VERSION 5.7 ;
  NOWIREEXTENSIONATPIN ON ;
  DIVIDERCHAR "/" ;
  BUSBITCHARS "[]" ;
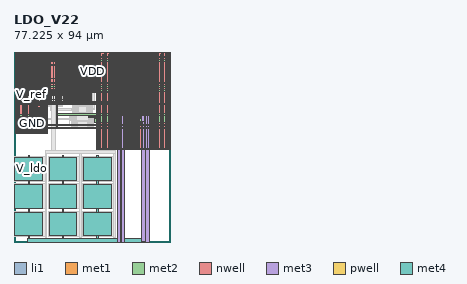
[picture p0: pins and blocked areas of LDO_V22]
MACRO LDO_V22
  CLASS BLOCK ;
  FOREIGN LDO_V22 ;
  ORIGIN -121.455 234.070 ;
  SIZE 77.225 BY 94.000 ;
  PIN V_ref
    ANTENNAGATEAREA 1.000000 ;
    PORT
      LAYER li1 ;
        RECT 125.885 -162.020 126.675 -161.850 ;
        RECT 127.175 -162.020 127.965 -161.850 ;
        RECT 125.885 -163.070 126.675 -162.900 ;
        RECT 127.175 -163.070 127.965 -162.900 ;
      LAYER met1 ;
        RECT 125.960 -161.820 126.600 -161.730 ;
        RECT 127.250 -161.820 127.890 -161.730 ;
        RECT 125.905 -162.050 126.655 -161.820 ;
        RECT 127.195 -162.050 127.945 -161.820 ;
        RECT 125.905 -163.100 126.655 -162.870 ;
        RECT 127.195 -163.100 127.945 -162.870 ;
        RECT 125.960 -163.190 126.600 -163.100 ;
        RECT 127.250 -163.190 127.890 -163.100 ;
      LAYER met2 ;
        RECT 122.295 -161.590 127.085 -160.520 ;
        RECT 126.765 -161.730 127.085 -161.590 ;
        RECT 125.960 -162.050 127.890 -161.730 ;
        RECT 126.720 -162.870 127.020 -162.050 ;
        RECT 125.960 -163.190 127.890 -162.870 ;
    END
  END V_ref
  PIN VDD
    ANTENNAGATEAREA 351.130005 ;
    ANTENNADIFFAREA 366.337494 ;
    PORT
      LAYER nwell ;
        RECT 122.220 -159.620 198.680 -140.070 ;
        RECT 122.955 -172.255 137.915 -165.300 ;
        RECT 162.180 -188.260 198.680 -159.620 ;
      LAYER li1 ;
        RECT 122.400 -140.420 162.090 -140.250 ;
        RECT 122.400 -153.120 122.570 -140.420 ;
        RECT 123.280 -140.930 124.120 -140.760 ;
        RECT 124.570 -140.930 125.410 -140.760 ;
        RECT 125.780 -140.930 128.070 -140.760 ;
        RECT 128.360 -140.930 129.360 -140.760 ;
        RECT 129.650 -140.930 130.650 -140.760 ;
        RECT 122.970 -146.185 123.140 -141.145 ;
        RECT 124.260 -146.185 124.430 -141.145 ;
        RECT 125.550 -146.185 125.720 -141.145 ;
        RECT 126.840 -146.400 127.010 -140.930 ;
        RECT 128.130 -146.185 128.300 -141.145 ;
        RECT 129.420 -146.185 129.590 -141.145 ;
        RECT 130.710 -146.185 130.880 -141.145 ;
        RECT 123.280 -146.570 124.120 -146.400 ;
        RECT 124.570 -146.570 125.410 -146.400 ;
        RECT 125.780 -146.570 128.070 -146.400 ;
        RECT 128.360 -146.570 129.360 -146.400 ;
        RECT 129.650 -146.570 130.650 -146.400 ;
        RECT 125.550 -152.365 125.720 -147.325 ;
        RECT 128.130 -152.365 128.300 -147.325 ;
        RECT 131.280 -153.120 131.450 -140.420 ;
        RECT 131.850 -140.760 132.020 -140.420 ;
        RECT 134.430 -140.760 134.600 -140.420 ;
        RECT 135.720 -140.760 135.890 -140.420 ;
        RECT 137.010 -140.760 137.180 -140.420 ;
        RECT 138.300 -140.760 138.470 -140.420 ;
        RECT 139.590 -140.760 139.760 -140.420 ;
        RECT 140.880 -140.760 141.050 -140.420 ;
        RECT 142.170 -140.760 142.340 -140.420 ;
        RECT 143.460 -140.760 143.630 -140.420 ;
        RECT 144.750 -140.760 144.920 -140.420 ;
        RECT 146.040 -140.760 146.210 -140.420 ;
        RECT 147.330 -140.760 147.500 -140.420 ;
        RECT 148.620 -140.760 148.790 -140.420 ;
        RECT 149.910 -140.760 150.080 -140.420 ;
        RECT 131.850 -140.930 150.080 -140.760 ;
        RECT 131.850 -146.400 132.020 -140.930 ;
        RECT 133.140 -146.185 133.310 -141.145 ;
        RECT 134.430 -146.400 134.600 -140.930 ;
        RECT 135.720 -146.400 135.890 -140.930 ;
        RECT 137.010 -146.400 137.180 -140.930 ;
        RECT 138.300 -146.400 138.470 -140.930 ;
        RECT 139.590 -146.400 139.760 -140.930 ;
        RECT 140.880 -146.400 141.050 -140.930 ;
        RECT 142.170 -146.400 142.340 -140.930 ;
        RECT 143.460 -146.400 143.630 -140.930 ;
        RECT 144.750 -146.400 144.920 -140.930 ;
        RECT 146.040 -146.400 146.210 -140.930 ;
        RECT 147.330 -146.400 147.500 -140.930 ;
        RECT 148.620 -146.400 148.790 -140.930 ;
        RECT 149.910 -146.400 150.080 -140.930 ;
        RECT 131.850 -146.570 150.080 -146.400 ;
        RECT 132.080 -147.110 133.080 -146.940 ;
        RECT 148.850 -147.110 149.850 -146.940 ;
        RECT 131.850 -152.365 132.020 -147.325 ;
        RECT 133.140 -152.365 133.310 -147.325 ;
        RECT 135.720 -152.365 135.890 -147.325 ;
        RECT 138.300 -152.365 138.470 -147.325 ;
        RECT 140.880 -152.365 141.050 -147.325 ;
        RECT 143.460 -152.365 143.630 -147.325 ;
        RECT 146.040 -152.365 146.210 -147.325 ;
        RECT 148.620 -152.365 148.790 -147.325 ;
        RECT 149.910 -152.365 150.080 -147.325 ;
        RECT 132.080 -152.750 133.080 -152.580 ;
        RECT 148.850 -152.750 149.850 -152.580 ;
        RECT 150.460 -153.120 150.650 -140.420 ;
        RECT 151.030 -140.760 151.200 -140.420 ;
        RECT 152.320 -140.760 152.490 -140.420 ;
        RECT 153.610 -140.760 153.780 -140.420 ;
        RECT 154.900 -140.760 155.070 -140.420 ;
        RECT 156.190 -140.760 156.360 -140.420 ;
        RECT 157.480 -140.760 157.650 -140.420 ;
        RECT 158.770 -140.760 158.940 -140.420 ;
        RECT 160.060 -140.760 160.230 -140.420 ;
        RECT 161.350 -140.760 161.520 -140.420 ;
        RECT 151.030 -140.930 161.520 -140.760 ;
        RECT 151.030 -146.400 151.200 -140.930 ;
        RECT 152.320 -146.400 152.490 -140.930 ;
        RECT 153.610 -146.400 153.780 -140.930 ;
        RECT 154.900 -146.400 155.070 -140.930 ;
        RECT 156.190 -146.400 156.360 -140.930 ;
        RECT 157.480 -146.400 157.650 -140.930 ;
        RECT 158.770 -146.400 158.940 -140.930 ;
        RECT 160.060 -146.400 160.230 -140.930 ;
        RECT 161.350 -146.400 161.520 -140.930 ;
        RECT 151.030 -146.570 161.520 -146.400 ;
        RECT 151.260 -147.110 152.260 -146.940 ;
        RECT 160.290 -147.110 161.290 -146.940 ;
        RECT 151.030 -152.365 151.200 -147.325 ;
        RECT 152.320 -152.365 152.490 -147.325 ;
        RECT 154.900 -152.365 155.070 -147.325 ;
        RECT 157.480 -152.365 157.650 -147.325 ;
        RECT 160.060 -152.365 160.230 -147.325 ;
        RECT 161.350 -152.365 161.520 -147.325 ;
        RECT 151.260 -152.750 152.260 -152.580 ;
        RECT 160.290 -152.750 161.290 -152.580 ;
        RECT 161.920 -153.120 162.090 -140.420 ;
        RECT 122.400 -153.290 162.090 -153.120 ;
        RECT 122.400 -158.760 122.570 -153.290 ;
        RECT 122.970 -158.545 123.140 -153.505 ;
        RECT 124.260 -158.760 124.430 -153.290 ;
        RECT 125.550 -158.760 125.720 -153.290 ;
        RECT 126.840 -158.760 127.010 -153.290 ;
        RECT 128.130 -158.760 128.300 -153.290 ;
        RECT 129.420 -158.760 129.590 -153.290 ;
        RECT 130.710 -158.545 130.880 -153.505 ;
        RECT 131.280 -158.760 131.450 -153.290 ;
        RECT 131.850 -158.760 132.020 -153.290 ;
        RECT 133.140 -158.760 133.310 -153.290 ;
        RECT 134.430 -158.760 134.600 -153.290 ;
        RECT 135.720 -158.760 135.890 -153.290 ;
        RECT 137.010 -158.760 137.180 -153.290 ;
        RECT 138.300 -158.760 138.470 -153.290 ;
        RECT 139.590 -158.760 139.760 -153.290 ;
        RECT 140.880 -158.760 141.050 -153.290 ;
        RECT 142.170 -158.760 142.340 -153.290 ;
        RECT 143.460 -158.760 143.630 -153.290 ;
        RECT 144.750 -158.760 144.920 -153.290 ;
        RECT 146.040 -158.760 146.210 -153.290 ;
        RECT 147.330 -158.760 147.500 -153.290 ;
        RECT 148.620 -158.760 148.790 -153.290 ;
        RECT 149.910 -158.760 150.080 -153.290 ;
        RECT 150.460 -158.760 150.650 -153.290 ;
        RECT 151.030 -158.760 151.200 -153.290 ;
        RECT 152.320 -158.760 152.490 -153.290 ;
        RECT 153.610 -158.760 153.780 -153.290 ;
        RECT 154.900 -158.760 155.070 -153.290 ;
        RECT 156.190 -158.760 156.360 -153.290 ;
        RECT 157.480 -158.760 157.650 -153.290 ;
        RECT 158.770 -158.760 158.940 -153.290 ;
        RECT 160.060 -158.760 160.230 -153.290 ;
        RECT 161.350 -158.760 161.520 -153.290 ;
        RECT 161.920 -158.760 162.090 -153.290 ;
        RECT 162.360 -140.420 198.500 -140.250 ;
        RECT 162.360 -156.830 162.530 -140.420 ;
        RECT 163.265 -140.930 164.055 -140.760 ;
        RECT 162.355 -157.470 162.530 -156.830 ;
        RECT 122.400 -158.930 162.090 -158.760 ;
        RECT 122.400 -159.270 122.570 -158.930 ;
        RECT 131.280 -159.270 131.450 -158.930 ;
        RECT 131.850 -159.270 132.020 -158.930 ;
        RECT 133.140 -159.270 133.310 -158.930 ;
        RECT 134.430 -159.270 134.600 -158.930 ;
        RECT 135.720 -159.270 135.890 -158.930 ;
        RECT 137.010 -159.270 137.180 -158.930 ;
        RECT 138.300 -159.270 138.470 -158.930 ;
        RECT 139.590 -159.270 139.760 -158.930 ;
        RECT 140.880 -159.270 141.050 -158.930 ;
        RECT 142.170 -159.270 142.340 -158.930 ;
        RECT 143.460 -159.270 143.630 -158.930 ;
        RECT 144.750 -159.270 144.920 -158.930 ;
        RECT 146.040 -159.270 146.210 -158.930 ;
        RECT 147.330 -159.270 147.500 -158.930 ;
        RECT 148.620 -159.270 148.790 -158.930 ;
        RECT 149.910 -159.270 150.080 -158.930 ;
        RECT 150.460 -159.270 150.650 -158.930 ;
        RECT 151.030 -159.270 151.200 -158.930 ;
        RECT 152.320 -159.270 152.490 -158.930 ;
        RECT 153.610 -159.270 153.780 -158.930 ;
        RECT 154.900 -159.270 155.070 -158.930 ;
        RECT 156.190 -159.270 156.360 -158.930 ;
        RECT 157.480 -159.270 157.650 -158.930 ;
        RECT 158.770 -159.270 158.940 -158.930 ;
        RECT 160.060 -159.270 160.230 -158.930 ;
        RECT 161.350 -159.270 161.520 -158.930 ;
        RECT 161.920 -159.270 162.090 -158.930 ;
        RECT 122.400 -159.440 162.090 -159.270 ;
        RECT 123.135 -165.650 137.735 -165.480 ;
        RECT 123.135 -171.905 123.305 -165.650 ;
        RECT 131.585 -166.585 132.425 -166.415 ;
        RECT 133.435 -166.460 134.275 -166.290 ;
        RECT 134.725 -166.460 135.565 -166.290 ;
        RECT 136.015 -166.460 136.855 -166.290 ;
        RECT 131.275 -167.340 131.445 -166.800 ;
        RECT 132.565 -167.340 132.735 -166.800 ;
        RECT 133.125 -167.305 133.295 -166.675 ;
        RECT 134.415 -167.305 134.585 -166.675 ;
        RECT 135.705 -167.305 135.875 -166.675 ;
        RECT 136.995 -167.305 137.165 -166.675 ;
        RECT 131.585 -167.725 132.425 -167.555 ;
        RECT 133.435 -167.690 134.275 -167.520 ;
        RECT 134.725 -167.690 135.565 -167.520 ;
        RECT 136.015 -167.690 136.855 -167.520 ;
        RECT 136.015 -168.230 136.855 -168.060 ;
        RECT 126.285 -169.115 126.455 -168.575 ;
        RECT 130.715 -169.200 130.885 -168.360 ;
        RECT 131.275 -169.020 131.445 -168.480 ;
        RECT 135.705 -169.075 135.875 -168.445 ;
        RECT 136.995 -169.075 137.165 -168.445 ;
        RECT 136.015 -169.460 136.855 -169.290 ;
        RECT 131.275 -169.830 133.300 -169.775 ;
        RECT 131.275 -169.945 136.855 -169.830 ;
        RECT 131.275 -170.915 131.445 -169.945 ;
        RECT 132.565 -170.915 132.735 -169.945 ;
        RECT 133.125 -170.000 136.855 -169.945 ;
        RECT 133.125 -170.915 133.295 -170.000 ;
        RECT 131.275 -171.060 133.295 -170.915 ;
        RECT 134.415 -171.060 134.585 -170.000 ;
        RECT 135.705 -170.845 135.875 -170.215 ;
        RECT 136.995 -170.845 137.165 -170.215 ;
        RECT 131.275 -171.085 136.855 -171.060 ;
        RECT 133.125 -171.230 136.855 -171.085 ;
        RECT 133.175 -171.905 133.370 -171.900 ;
        RECT 137.565 -171.905 137.735 -165.650 ;
        RECT 123.135 -172.075 137.735 -171.905 ;
        RECT 162.360 -187.910 162.530 -157.470 ;
        RECT 162.930 -187.185 163.100 -141.145 ;
        RECT 164.220 -187.185 164.390 -141.145 ;
        RECT 166.800 -187.185 166.970 -141.145 ;
        RECT 169.380 -187.185 169.550 -141.145 ;
        RECT 171.960 -187.185 172.130 -141.145 ;
        RECT 174.540 -187.185 174.710 -141.145 ;
        RECT 177.120 -187.185 177.290 -141.145 ;
        RECT 179.700 -187.185 179.870 -141.145 ;
        RECT 182.280 -187.185 182.450 -141.145 ;
        RECT 184.860 -187.185 185.030 -141.145 ;
        RECT 187.440 -187.185 187.610 -141.145 ;
        RECT 190.020 -187.185 190.190 -141.145 ;
        RECT 192.600 -187.185 192.770 -141.145 ;
        RECT 195.180 -187.185 195.350 -141.145 ;
        RECT 163.265 -187.570 164.055 -187.400 ;
        RECT 198.330 -187.910 198.500 -140.420 ;
        RECT 162.360 -188.080 198.500 -187.910 ;
      LAYER met1 ;
        RECT 122.320 -140.170 122.640 -140.165 ;
        RECT 122.320 -140.490 198.235 -140.170 ;
        RECT 122.320 -140.730 122.640 -140.490 ;
        RECT 122.940 -140.730 123.170 -140.490 ;
        RECT 124.230 -140.730 124.460 -140.490 ;
        RECT 125.520 -140.730 125.750 -140.490 ;
        RECT 128.100 -140.730 128.330 -140.490 ;
        RECT 129.390 -140.730 129.620 -140.490 ;
        RECT 130.680 -140.730 130.910 -140.490 ;
        RECT 131.205 -140.730 131.525 -140.490 ;
        RECT 122.320 -140.960 126.655 -140.730 ;
        RECT 127.195 -140.960 131.525 -140.730 ;
        RECT 122.320 -146.370 122.640 -140.960 ;
        RECT 122.940 -146.370 123.170 -140.960 ;
        RECT 124.230 -146.370 124.460 -140.960 ;
        RECT 125.520 -142.290 125.750 -140.960 ;
        RECT 128.100 -142.290 128.330 -140.960 ;
        RECT 125.475 -142.930 125.795 -142.290 ;
        RECT 128.055 -142.930 128.375 -142.290 ;
        RECT 125.520 -144.020 125.750 -142.930 ;
        RECT 128.100 -144.020 128.330 -142.930 ;
        RECT 125.475 -144.660 125.795 -144.020 ;
        RECT 128.055 -144.660 128.375 -144.020 ;
        RECT 125.520 -146.370 125.750 -144.660 ;
        RECT 128.100 -146.370 128.330 -144.660 ;
        RECT 129.390 -146.370 129.620 -140.960 ;
        RECT 130.680 -146.370 130.910 -140.960 ;
        RECT 131.205 -146.370 131.525 -140.960 ;
        RECT 131.820 -140.730 132.050 -140.490 ;
        RECT 133.110 -140.730 133.350 -140.490 ;
        RECT 131.820 -140.960 133.390 -140.730 ;
        RECT 135.645 -140.840 135.965 -140.490 ;
        RECT 138.225 -140.840 138.545 -140.490 ;
        RECT 140.805 -140.840 141.125 -140.490 ;
        RECT 143.385 -140.840 143.705 -140.490 ;
        RECT 145.965 -140.840 146.285 -140.490 ;
        RECT 148.545 -140.730 148.865 -140.490 ;
        RECT 149.830 -140.730 150.150 -140.490 ;
        RECT 148.545 -140.840 150.150 -140.730 ;
        RECT 131.820 -142.290 132.050 -140.960 ;
        RECT 133.110 -142.290 133.350 -140.960 ;
        RECT 135.690 -142.290 135.920 -140.840 ;
        RECT 138.270 -142.290 138.500 -140.840 ;
        RECT 140.850 -142.285 141.080 -140.840 ;
        RECT 131.775 -142.930 132.095 -142.290 ;
        RECT 133.065 -142.930 133.385 -142.290 ;
        RECT 135.645 -142.930 135.965 -142.290 ;
        RECT 138.220 -142.930 138.540 -142.290 ;
        RECT 140.805 -142.925 141.125 -142.285 ;
        RECT 143.430 -142.290 143.660 -140.840 ;
        RECT 146.010 -142.290 146.240 -140.840 ;
        RECT 148.545 -140.960 150.110 -140.840 ;
        RECT 148.590 -142.290 148.820 -140.960 ;
        RECT 149.880 -142.290 150.110 -140.960 ;
        RECT 131.820 -144.020 132.050 -142.930 ;
        RECT 133.110 -144.020 133.350 -142.930 ;
        RECT 135.690 -144.020 135.920 -142.930 ;
        RECT 138.270 -144.020 138.500 -142.930 ;
        RECT 140.850 -144.020 141.080 -142.925 ;
        RECT 143.385 -142.930 143.705 -142.290 ;
        RECT 145.965 -142.930 146.285 -142.290 ;
        RECT 148.545 -142.930 148.865 -142.290 ;
        RECT 149.835 -142.930 150.155 -142.290 ;
        RECT 143.430 -144.020 143.660 -142.930 ;
        RECT 146.010 -144.020 146.240 -142.930 ;
        RECT 148.590 -144.020 148.820 -142.930 ;
        RECT 149.880 -144.020 150.110 -142.930 ;
        RECT 131.775 -144.660 132.095 -144.020 ;
        RECT 133.065 -144.660 133.385 -144.020 ;
        RECT 135.645 -144.660 135.965 -144.020 ;
        RECT 138.225 -144.660 138.545 -144.020 ;
        RECT 140.805 -144.660 141.125 -144.020 ;
        RECT 143.385 -144.660 143.705 -144.020 ;
        RECT 145.965 -144.660 146.285 -144.020 ;
        RECT 148.545 -144.660 148.865 -144.020 ;
        RECT 149.835 -144.660 150.155 -144.020 ;
        RECT 122.320 -146.600 126.655 -146.370 ;
        RECT 127.195 -146.600 131.525 -146.370 ;
        RECT 122.320 -159.535 122.640 -146.600 ;
        RECT 122.940 -153.320 124.075 -153.090 ;
        RECT 122.940 -158.730 123.170 -153.320 ;
        RECT 125.520 -155.195 125.750 -146.600 ;
        RECT 128.100 -155.195 128.330 -146.600 ;
        RECT 129.775 -153.320 130.910 -153.090 ;
        RECT 125.475 -155.835 125.795 -155.195 ;
        RECT 128.050 -155.515 128.370 -155.195 ;
        RECT 128.055 -155.835 128.375 -155.515 ;
        RECT 125.520 -156.830 125.750 -155.835 ;
        RECT 128.100 -156.830 128.330 -155.835 ;
        RECT 125.475 -157.470 125.795 -156.830 ;
        RECT 128.055 -157.470 128.375 -156.830 ;
        RECT 122.940 -158.960 124.075 -158.730 ;
        RECT 125.520 -159.440 125.750 -157.470 ;
        RECT 128.100 -159.440 128.330 -157.470 ;
        RECT 130.680 -158.730 130.910 -153.320 ;
        RECT 129.775 -158.960 130.910 -158.730 ;
        RECT 130.680 -158.965 130.910 -158.960 ;
        RECT 131.205 -159.215 131.525 -146.600 ;
        RECT 131.820 -146.370 132.050 -144.660 ;
        RECT 133.110 -146.370 133.350 -144.660 ;
        RECT 131.820 -146.600 133.350 -146.370 ;
        RECT 131.820 -146.910 132.050 -146.600 ;
        RECT 133.110 -146.910 133.350 -146.600 ;
        RECT 131.820 -147.140 133.350 -146.910 ;
        RECT 131.820 -152.550 132.050 -147.140 ;
        RECT 133.110 -147.510 133.350 -147.140 ;
        RECT 133.110 -152.550 133.340 -147.510 ;
        RECT 131.820 -152.780 133.340 -152.550 ;
        RECT 131.820 -153.090 132.050 -152.780 ;
        RECT 133.110 -153.090 133.340 -152.780 ;
        RECT 131.820 -153.320 133.340 -153.090 ;
        RECT 131.820 -155.195 132.050 -153.320 ;
        RECT 133.110 -155.195 133.340 -153.320 ;
        RECT 135.690 -155.195 135.920 -144.660 ;
        RECT 138.270 -155.195 138.500 -144.660 ;
        RECT 140.850 -155.195 141.080 -144.660 ;
        RECT 143.430 -155.195 143.660 -144.660 ;
        RECT 146.010 -155.195 146.240 -144.660 ;
        RECT 148.590 -146.370 148.820 -144.660 ;
        RECT 149.880 -146.370 150.110 -144.660 ;
        RECT 148.590 -146.600 150.110 -146.370 ;
        RECT 148.590 -146.910 148.820 -146.600 ;
        RECT 149.880 -146.910 150.110 -146.600 ;
        RECT 148.590 -147.140 150.110 -146.910 ;
        RECT 148.590 -152.550 148.820 -147.140 ;
        RECT 149.880 -152.550 150.110 -147.140 ;
        RECT 148.590 -152.780 150.110 -152.550 ;
        RECT 148.590 -153.090 148.820 -152.780 ;
        RECT 149.880 -153.090 150.110 -152.780 ;
        RECT 148.590 -153.320 150.110 -153.090 ;
        RECT 148.590 -155.195 148.820 -153.320 ;
        RECT 149.880 -155.195 150.110 -153.320 ;
        RECT 131.775 -155.835 132.095 -155.195 ;
        RECT 133.065 -155.835 133.385 -155.195 ;
        RECT 135.645 -155.835 135.965 -155.195 ;
        RECT 138.225 -155.835 138.545 -155.195 ;
        RECT 140.805 -155.835 141.125 -155.195 ;
        RECT 143.385 -155.835 143.705 -155.195 ;
        RECT 145.965 -155.835 146.285 -155.195 ;
        RECT 148.545 -155.835 148.865 -155.195 ;
        RECT 149.835 -155.835 150.155 -155.195 ;
        RECT 131.820 -156.830 132.050 -155.835 ;
        RECT 133.110 -156.830 133.340 -155.835 ;
        RECT 135.690 -156.830 135.920 -155.835 ;
        RECT 138.270 -156.830 138.500 -155.835 ;
        RECT 140.850 -156.830 141.080 -155.835 ;
        RECT 143.430 -156.830 143.660 -155.835 ;
        RECT 146.010 -156.830 146.240 -155.835 ;
        RECT 148.590 -156.830 148.820 -155.835 ;
        RECT 149.880 -156.830 150.110 -155.835 ;
        RECT 131.775 -157.470 132.095 -156.830 ;
        RECT 133.065 -157.470 133.385 -156.830 ;
        RECT 135.645 -157.470 135.965 -156.830 ;
        RECT 138.225 -157.470 138.545 -156.830 ;
        RECT 140.805 -157.470 141.125 -156.830 ;
        RECT 143.385 -157.470 143.705 -156.830 ;
        RECT 145.965 -157.470 146.285 -156.830 ;
        RECT 148.545 -157.470 148.865 -156.830 ;
        RECT 149.835 -157.470 150.155 -156.830 ;
        RECT 131.820 -158.730 132.050 -157.470 ;
        RECT 133.110 -158.730 133.340 -157.470 ;
        RECT 131.820 -158.865 133.385 -158.730 ;
        RECT 135.690 -158.865 135.920 -157.470 ;
        RECT 138.270 -158.865 138.500 -157.470 ;
        RECT 140.850 -158.865 141.080 -157.470 ;
        RECT 143.430 -158.865 143.660 -157.470 ;
        RECT 146.010 -158.865 146.240 -157.470 ;
        RECT 148.590 -158.730 148.820 -157.470 ;
        RECT 149.880 -158.730 150.110 -157.470 ;
        RECT 148.545 -158.865 150.110 -158.730 ;
        RECT 131.775 -158.960 133.385 -158.865 ;
        RECT 131.775 -159.215 132.095 -158.960 ;
        RECT 133.065 -159.215 133.385 -158.960 ;
        RECT 135.645 -159.215 135.965 -158.865 ;
        RECT 138.225 -159.215 138.545 -158.865 ;
        RECT 129.945 -159.485 139.120 -159.215 ;
        RECT 140.805 -159.225 141.125 -158.865 ;
        RECT 143.385 -159.225 143.705 -158.865 ;
        RECT 145.965 -159.225 146.285 -158.865 ;
        RECT 148.545 -158.960 150.150 -158.865 ;
        RECT 148.545 -159.225 148.865 -158.960 ;
        RECT 149.830 -159.225 150.150 -158.960 ;
        RECT 131.775 -159.505 132.095 -159.485 ;
        RECT 133.065 -159.505 133.385 -159.485 ;
        RECT 135.645 -159.505 135.965 -159.485 ;
        RECT 138.225 -159.505 138.545 -159.485 ;
        RECT 140.100 -159.500 150.150 -159.225 ;
        RECT 150.400 -159.450 150.720 -140.490 ;
        RECT 151.000 -140.730 151.225 -140.490 ;
        RECT 152.290 -140.730 152.520 -140.490 ;
        RECT 151.000 -140.960 152.520 -140.730 ;
        RECT 151.000 -141.165 151.225 -140.960 ;
        RECT 151.000 -142.290 151.230 -141.165 ;
        RECT 152.290 -142.290 152.520 -140.960 ;
        RECT 154.870 -142.290 155.100 -140.490 ;
        RECT 157.450 -142.290 157.680 -140.490 ;
        RECT 160.030 -140.730 160.260 -140.490 ;
        RECT 161.320 -140.730 161.550 -140.490 ;
        RECT 160.030 -140.960 161.550 -140.730 ;
        RECT 160.030 -142.290 160.260 -140.960 ;
        RECT 161.320 -142.290 161.550 -140.960 ;
        RECT 150.955 -142.930 151.275 -142.290 ;
        RECT 152.245 -142.930 152.565 -142.290 ;
        RECT 154.825 -142.930 155.145 -142.290 ;
        RECT 157.405 -142.930 157.725 -142.290 ;
        RECT 159.985 -142.930 160.305 -142.290 ;
        RECT 161.275 -142.930 161.595 -142.290 ;
        RECT 151.000 -144.020 151.230 -142.930 ;
        RECT 152.290 -144.020 152.520 -142.930 ;
        RECT 154.870 -144.020 155.100 -142.930 ;
        RECT 157.450 -144.020 157.680 -142.930 ;
        RECT 160.030 -144.020 160.260 -142.930 ;
        RECT 161.320 -144.020 161.550 -142.930 ;
        RECT 150.955 -144.660 151.275 -144.020 ;
        RECT 152.245 -144.660 152.565 -144.020 ;
        RECT 154.825 -144.660 155.145 -144.020 ;
        RECT 157.405 -144.660 157.725 -144.020 ;
        RECT 159.985 -144.660 160.305 -144.020 ;
        RECT 161.275 -144.660 161.595 -144.020 ;
        RECT 151.000 -146.370 151.230 -144.660 ;
        RECT 152.290 -146.370 152.520 -144.660 ;
        RECT 151.000 -146.600 152.520 -146.370 ;
        RECT 151.000 -146.910 151.230 -146.600 ;
        RECT 152.290 -146.910 152.520 -146.600 ;
        RECT 151.000 -147.140 152.520 -146.910 ;
        RECT 151.000 -152.550 151.230 -147.140 ;
        RECT 152.290 -152.550 152.520 -147.140 ;
        RECT 151.000 -152.780 152.520 -152.550 ;
        RECT 151.000 -153.530 151.230 -152.780 ;
        RECT 152.290 -155.195 152.520 -152.780 ;
        RECT 154.870 -155.195 155.100 -144.660 ;
        RECT 157.450 -155.195 157.680 -144.660 ;
        RECT 160.030 -146.370 160.260 -144.660 ;
        RECT 161.320 -146.370 161.550 -144.660 ;
        RECT 160.030 -146.600 161.550 -146.370 ;
        RECT 160.030 -146.910 160.260 -146.600 ;
        RECT 161.320 -146.910 161.550 -146.600 ;
        RECT 160.030 -147.140 161.550 -146.910 ;
        RECT 160.030 -152.550 160.260 -147.140 ;
        RECT 161.320 -152.550 161.550 -147.140 ;
        RECT 160.030 -152.780 161.550 -152.550 ;
        RECT 160.030 -155.195 160.260 -152.780 ;
        RECT 161.320 -153.485 161.550 -152.780 ;
        RECT 152.245 -155.835 152.565 -155.195 ;
        RECT 154.825 -155.835 155.145 -155.195 ;
        RECT 157.405 -155.835 157.725 -155.195 ;
        RECT 159.975 -155.835 160.295 -155.195 ;
        RECT 152.290 -156.830 152.520 -155.835 ;
        RECT 154.870 -156.830 155.100 -155.835 ;
        RECT 157.450 -156.830 157.680 -155.835 ;
        RECT 160.030 -156.830 160.260 -155.835 ;
        RECT 152.245 -157.470 152.565 -156.830 ;
        RECT 154.825 -157.470 155.145 -156.830 ;
        RECT 157.405 -157.470 157.725 -156.830 ;
        RECT 159.975 -157.470 160.295 -156.830 ;
        RECT 152.290 -158.865 152.520 -157.470 ;
        RECT 140.805 -159.505 141.125 -159.500 ;
        RECT 143.385 -159.505 143.705 -159.500 ;
        RECT 145.965 -159.505 146.285 -159.500 ;
        RECT 148.545 -159.505 148.865 -159.500 ;
        RECT 149.830 -159.505 150.150 -159.500 ;
        RECT 152.240 -159.505 152.560 -158.865 ;
        RECT 154.870 -158.870 155.100 -157.470 ;
        RECT 157.450 -158.870 157.680 -157.470 ;
        RECT 160.030 -158.865 160.260 -157.470 ;
        RECT 154.820 -159.510 155.140 -158.870 ;
        RECT 157.405 -159.510 157.725 -158.870 ;
        RECT 159.975 -159.505 160.295 -158.865 ;
        RECT 161.815 -159.505 162.575 -140.490 ;
        RECT 162.900 -140.730 163.130 -140.490 ;
        RECT 164.190 -140.730 164.420 -140.490 ;
        RECT 162.900 -140.960 164.420 -140.730 ;
        RECT 162.900 -142.290 163.130 -140.960 ;
        RECT 164.190 -142.290 164.420 -140.960 ;
        RECT 166.770 -142.290 167.000 -140.490 ;
        RECT 169.350 -142.290 169.580 -140.490 ;
        RECT 171.930 -142.290 172.160 -140.490 ;
        RECT 174.510 -142.290 174.740 -140.490 ;
        RECT 177.090 -142.290 177.320 -140.490 ;
        RECT 179.670 -142.290 179.900 -140.490 ;
        RECT 182.250 -142.290 182.480 -140.490 ;
        RECT 184.830 -142.290 185.060 -140.490 ;
        RECT 187.410 -142.290 187.640 -140.490 ;
        RECT 189.990 -142.290 190.220 -140.490 ;
        RECT 192.570 -142.290 192.800 -140.490 ;
        RECT 162.855 -142.930 163.175 -142.290 ;
        RECT 164.145 -142.930 164.465 -142.290 ;
        RECT 166.725 -142.930 167.045 -142.290 ;
        RECT 169.305 -142.930 169.625 -142.290 ;
        RECT 171.885 -142.930 172.205 -142.290 ;
        RECT 174.465 -142.930 174.785 -142.290 ;
        RECT 177.045 -142.930 177.365 -142.290 ;
        RECT 179.625 -142.930 179.945 -142.290 ;
        RECT 182.205 -142.930 182.525 -142.290 ;
        RECT 184.785 -142.930 185.105 -142.290 ;
        RECT 187.365 -142.930 187.685 -142.290 ;
        RECT 189.945 -142.930 190.265 -142.290 ;
        RECT 192.525 -142.930 192.845 -142.290 ;
        RECT 195.150 -142.295 195.380 -140.490 ;
        RECT 162.900 -144.020 163.130 -142.930 ;
        RECT 164.190 -144.020 164.420 -142.930 ;
        RECT 166.770 -144.020 167.000 -142.930 ;
        RECT 169.350 -144.020 169.580 -142.930 ;
        RECT 171.930 -144.020 172.160 -142.930 ;
        RECT 174.510 -144.020 174.740 -142.930 ;
        RECT 177.090 -144.020 177.320 -142.930 ;
        RECT 179.670 -144.020 179.900 -142.930 ;
        RECT 182.250 -144.020 182.480 -142.930 ;
        RECT 184.830 -144.020 185.060 -142.930 ;
        RECT 187.410 -144.020 187.640 -142.930 ;
        RECT 189.990 -144.020 190.220 -142.930 ;
        RECT 192.570 -144.020 192.800 -142.930 ;
        RECT 195.105 -142.935 195.425 -142.295 ;
        RECT 198.255 -142.930 198.575 -142.290 ;
        RECT 195.150 -144.020 195.380 -142.935 ;
        RECT 162.855 -144.660 163.175 -144.020 ;
        RECT 164.145 -144.660 164.465 -144.020 ;
        RECT 166.725 -144.660 167.045 -144.020 ;
        RECT 169.305 -144.660 169.625 -144.020 ;
        RECT 171.885 -144.660 172.205 -144.020 ;
        RECT 174.465 -144.660 174.785 -144.020 ;
        RECT 177.045 -144.660 177.365 -144.020 ;
        RECT 179.625 -144.660 179.945 -144.020 ;
        RECT 182.205 -144.660 182.525 -144.020 ;
        RECT 184.785 -144.660 185.105 -144.020 ;
        RECT 187.365 -144.660 187.685 -144.020 ;
        RECT 189.945 -144.660 190.265 -144.020 ;
        RECT 192.525 -144.660 192.845 -144.020 ;
        RECT 195.105 -144.660 195.425 -144.020 ;
        RECT 198.255 -144.660 198.575 -144.020 ;
        RECT 162.900 -155.195 163.130 -144.660 ;
        RECT 164.190 -155.195 164.420 -144.660 ;
        RECT 166.770 -155.195 167.000 -144.660 ;
        RECT 169.350 -155.195 169.580 -144.660 ;
        RECT 171.930 -155.195 172.160 -144.660 ;
        RECT 174.510 -155.195 174.740 -144.660 ;
        RECT 177.090 -155.195 177.320 -144.660 ;
        RECT 179.670 -155.195 179.900 -144.660 ;
        RECT 182.250 -155.195 182.480 -144.660 ;
        RECT 184.830 -155.195 185.060 -144.660 ;
        RECT 187.410 -155.195 187.640 -144.660 ;
        RECT 189.990 -155.195 190.220 -144.660 ;
        RECT 192.570 -155.195 192.800 -144.660 ;
        RECT 195.150 -155.195 195.380 -144.660 ;
        RECT 162.855 -155.835 163.175 -155.195 ;
        RECT 164.145 -155.835 164.465 -155.195 ;
        RECT 166.725 -155.835 167.045 -155.195 ;
        RECT 169.305 -155.835 169.625 -155.195 ;
        RECT 171.885 -155.835 172.205 -155.195 ;
        RECT 174.465 -155.835 174.785 -155.195 ;
        RECT 177.045 -155.835 177.365 -155.195 ;
        RECT 179.625 -155.835 179.945 -155.195 ;
        RECT 182.205 -155.835 182.525 -155.195 ;
        RECT 184.785 -155.835 185.105 -155.195 ;
        RECT 187.365 -155.835 187.685 -155.195 ;
        RECT 189.945 -155.835 190.265 -155.195 ;
        RECT 192.525 -155.835 192.845 -155.195 ;
        RECT 195.105 -155.835 195.425 -155.195 ;
        RECT 162.900 -156.830 163.130 -155.835 ;
        RECT 164.190 -156.830 164.420 -155.835 ;
        RECT 166.770 -156.830 167.000 -155.835 ;
        RECT 169.350 -156.830 169.580 -155.835 ;
        RECT 171.930 -156.830 172.160 -155.835 ;
        RECT 174.510 -156.830 174.740 -155.835 ;
        RECT 177.090 -156.830 177.320 -155.835 ;
        RECT 179.670 -156.830 179.900 -155.835 ;
        RECT 182.250 -156.830 182.480 -155.835 ;
        RECT 184.830 -156.830 185.060 -155.835 ;
        RECT 187.410 -156.830 187.640 -155.835 ;
        RECT 189.990 -156.830 190.220 -155.835 ;
        RECT 192.570 -156.830 192.800 -155.835 ;
        RECT 195.150 -156.830 195.380 -155.835 ;
        RECT 162.855 -157.470 163.175 -156.830 ;
        RECT 164.145 -157.470 164.465 -156.830 ;
        RECT 166.725 -157.470 167.045 -156.830 ;
        RECT 169.305 -157.470 169.625 -156.830 ;
        RECT 171.885 -157.470 172.205 -156.830 ;
        RECT 174.465 -157.470 174.785 -156.830 ;
        RECT 177.045 -157.470 177.365 -156.830 ;
        RECT 179.625 -157.470 179.945 -156.830 ;
        RECT 182.205 -157.470 182.525 -156.830 ;
        RECT 184.785 -157.470 185.105 -156.830 ;
        RECT 187.365 -157.470 187.685 -156.830 ;
        RECT 189.945 -157.470 190.265 -156.830 ;
        RECT 192.525 -157.470 192.845 -156.830 ;
        RECT 195.105 -157.470 195.425 -156.830 ;
        RECT 162.900 -158.865 163.130 -157.470 ;
        RECT 164.190 -158.865 164.420 -157.470 ;
        RECT 166.770 -158.865 167.000 -157.470 ;
        RECT 169.350 -158.865 169.580 -157.470 ;
        RECT 171.930 -158.865 172.160 -157.470 ;
        RECT 174.510 -158.865 174.740 -157.470 ;
        RECT 177.090 -158.865 177.320 -157.470 ;
        RECT 162.855 -159.505 163.175 -158.865 ;
        RECT 164.145 -159.505 164.465 -158.865 ;
        RECT 166.725 -159.505 167.045 -158.865 ;
        RECT 169.305 -159.505 169.625 -158.865 ;
        RECT 171.885 -159.505 172.205 -158.865 ;
        RECT 174.465 -159.505 174.785 -158.865 ;
        RECT 177.045 -159.505 177.365 -158.865 ;
        RECT 179.670 -158.870 179.900 -157.470 ;
        RECT 182.250 -158.865 182.480 -157.470 ;
        RECT 184.830 -158.865 185.060 -157.470 ;
        RECT 187.410 -158.865 187.640 -157.470 ;
        RECT 189.990 -158.865 190.220 -157.470 ;
        RECT 192.570 -158.865 192.800 -157.470 ;
        RECT 195.150 -158.865 195.380 -157.470 ;
        RECT 162.900 -165.380 163.130 -159.505 ;
        RECT 164.190 -165.380 164.420 -159.505 ;
        RECT 166.770 -165.380 167.000 -159.505 ;
        RECT 169.350 -165.380 169.580 -159.505 ;
        RECT 171.930 -165.380 172.160 -159.505 ;
        RECT 174.510 -165.380 174.740 -159.505 ;
        RECT 177.090 -165.380 177.320 -159.505 ;
        RECT 179.625 -159.510 179.945 -158.870 ;
        RECT 182.205 -159.505 182.525 -158.865 ;
        RECT 184.785 -159.505 185.105 -158.865 ;
        RECT 187.365 -159.505 187.685 -158.865 ;
        RECT 189.945 -159.505 190.265 -158.865 ;
        RECT 192.525 -159.505 192.845 -158.865 ;
        RECT 195.105 -159.505 195.425 -158.865 ;
        RECT 179.670 -165.380 179.900 -159.510 ;
        RECT 182.250 -165.380 182.480 -159.505 ;
        RECT 184.830 -165.380 185.060 -159.505 ;
        RECT 187.410 -165.380 187.640 -159.505 ;
        RECT 189.990 -165.380 190.220 -159.505 ;
        RECT 192.570 -165.380 192.800 -159.505 ;
        RECT 195.150 -165.380 195.380 -159.505 ;
        RECT 123.055 -165.385 123.375 -165.380 ;
        RECT 130.920 -165.385 131.240 -165.380 ;
        RECT 133.050 -165.385 133.370 -165.380 ;
        RECT 135.630 -165.385 135.950 -165.380 ;
        RECT 136.685 -165.385 137.230 -165.380 ;
        RECT 123.055 -165.725 137.800 -165.385 ;
        RECT 123.055 -172.075 123.375 -165.725 ;
        RECT 126.190 -166.025 126.510 -165.725 ;
        RECT 130.685 -166.020 131.475 -165.725 ;
        RECT 133.050 -166.020 133.370 -165.725 ;
        RECT 135.630 -166.020 135.950 -165.725 ;
        RECT 136.910 -166.020 137.230 -165.725 ;
        RECT 126.255 -171.840 126.485 -166.025 ;
        RECT 130.685 -171.825 130.915 -166.020 ;
        RECT 131.245 -166.385 131.475 -166.020 ;
        RECT 133.095 -166.260 133.325 -166.020 ;
        RECT 135.675 -166.260 135.905 -166.020 ;
        RECT 136.965 -166.260 137.195 -166.020 ;
        RECT 133.095 -166.385 137.195 -166.260 ;
        RECT 131.245 -166.490 137.195 -166.385 ;
        RECT 131.245 -166.615 133.325 -166.490 ;
        RECT 131.245 -167.490 131.475 -166.615 ;
        RECT 132.535 -167.490 132.765 -166.615 ;
        RECT 133.095 -167.490 133.325 -166.615 ;
        RECT 134.385 -167.490 134.615 -166.490 ;
        RECT 135.675 -167.490 135.905 -166.490 ;
        RECT 136.965 -167.490 137.195 -166.490 ;
        RECT 131.245 -167.755 137.195 -167.490 ;
        RECT 131.245 -171.825 131.475 -167.755 ;
        RECT 126.075 -172.130 126.665 -171.840 ;
        RECT 130.685 -172.115 131.475 -171.825 ;
        RECT 133.095 -171.780 133.325 -167.755 ;
        RECT 135.675 -168.030 135.905 -167.755 ;
        RECT 136.965 -168.030 137.195 -167.755 ;
        RECT 135.675 -168.265 137.195 -168.030 ;
        RECT 135.675 -169.255 135.905 -168.265 ;
        RECT 136.965 -169.255 137.195 -168.265 ;
        RECT 135.675 -169.490 137.195 -169.255 ;
        RECT 135.675 -169.795 135.905 -169.490 ;
        RECT 136.965 -169.795 137.195 -169.490 ;
        RECT 135.675 -170.030 137.195 -169.795 ;
        RECT 135.675 -171.030 135.905 -170.030 ;
        RECT 136.965 -171.030 137.195 -170.030 ;
        RECT 135.675 -171.265 137.195 -171.030 ;
        RECT 133.095 -172.130 133.430 -171.780 ;
        RECT 135.675 -171.845 135.905 -171.265 ;
        RECT 136.965 -171.845 137.195 -171.265 ;
        RECT 137.480 -171.845 137.800 -165.725 ;
        RECT 162.855 -166.020 163.175 -165.380 ;
        RECT 164.145 -166.020 164.465 -165.380 ;
        RECT 166.725 -166.020 167.045 -165.380 ;
        RECT 169.305 -166.020 169.625 -165.380 ;
        RECT 171.885 -166.020 172.205 -165.380 ;
        RECT 174.465 -166.020 174.785 -165.380 ;
        RECT 177.045 -166.020 177.365 -165.380 ;
        RECT 179.625 -166.020 179.945 -165.380 ;
        RECT 182.205 -166.020 182.525 -165.380 ;
        RECT 184.785 -166.020 185.105 -165.380 ;
        RECT 187.365 -166.020 187.685 -165.380 ;
        RECT 189.945 -166.020 190.265 -165.380 ;
        RECT 192.525 -166.020 192.845 -165.380 ;
        RECT 195.105 -166.020 195.425 -165.380 ;
        RECT 135.570 -172.135 136.160 -171.845 ;
        RECT 136.800 -172.135 137.800 -171.845 ;
        RECT 137.480 -172.160 137.800 -172.135 ;
        RECT 162.900 -187.835 163.130 -166.020 ;
        RECT 163.285 -187.600 164.035 -187.370 ;
        RECT 164.190 -187.835 164.420 -166.020 ;
        RECT 166.770 -187.835 167.000 -166.020 ;
        RECT 169.350 -187.835 169.580 -166.020 ;
        RECT 171.930 -187.835 172.160 -166.020 ;
        RECT 162.690 -187.840 163.340 -187.835 ;
        RECT 163.990 -187.840 164.630 -187.835 ;
        RECT 166.560 -187.840 167.200 -187.835 ;
        RECT 169.140 -187.840 169.795 -187.835 ;
        RECT 171.680 -187.840 172.320 -187.835 ;
        RECT 174.510 -187.840 174.740 -166.020 ;
        RECT 177.090 -187.840 177.320 -166.020 ;
        RECT 179.670 -187.840 179.900 -166.020 ;
        RECT 182.250 -187.840 182.480 -166.020 ;
        RECT 184.830 -187.840 185.060 -166.020 ;
        RECT 187.410 -187.835 187.640 -166.020 ;
        RECT 189.990 -187.835 190.220 -166.020 ;
        RECT 192.570 -187.835 192.800 -166.020 ;
        RECT 195.150 -187.835 195.380 -166.020 ;
        RECT 187.205 -187.840 187.845 -187.835 ;
        RECT 189.785 -187.840 190.425 -187.835 ;
        RECT 192.365 -187.840 193.005 -187.835 ;
        RECT 194.950 -187.840 195.590 -187.835 ;
        RECT 162.690 -187.875 198.170 -187.840 ;
        RECT 162.690 -188.115 198.185 -187.875 ;
        RECT 162.690 -188.155 198.170 -188.115 ;
      LAYER met2 ;
        RECT 122.220 -140.510 198.500 -140.070 ;
        RECT 122.220 -140.840 163.940 -140.510 ;
        RECT 140.805 -142.290 141.125 -142.285 ;
        RECT 122.220 -142.930 198.680 -142.290 ;
        RECT 195.105 -142.935 195.425 -142.930 ;
        RECT 122.220 -144.660 198.680 -144.020 ;
        RECT 122.220 -155.835 198.680 -155.195 ;
        RECT 122.220 -157.470 198.680 -156.830 ;
        RECT 122.220 -159.505 198.680 -158.865 ;
        RECT 122.220 -159.535 122.640 -159.505 ;
        RECT 154.820 -159.510 155.140 -159.505 ;
        RECT 157.405 -159.510 157.725 -159.505 ;
        RECT 179.625 -159.510 179.945 -159.505 ;
        RECT 122.220 -166.020 198.680 -165.380 ;
        RECT 123.055 -166.025 123.375 -166.020 ;
        RECT 126.190 -166.025 126.510 -166.020 ;
        RECT 137.480 -166.025 137.800 -166.020 ;
        RECT 122.220 -171.740 138.240 -171.100 ;
        RECT 162.180 -188.260 198.500 -187.740 ;
      LAYER met3 ;
        RECT 122.220 -159.305 122.685 -140.070 ;
        RECT 122.985 -159.305 123.450 -140.070 ;
        RECT 123.750 -159.305 124.215 -140.070 ;
        RECT 124.515 -159.305 124.980 -140.070 ;
        RECT 125.280 -159.305 125.745 -140.070 ;
        RECT 126.045 -159.305 126.510 -140.070 ;
        RECT 126.810 -159.305 127.275 -140.070 ;
        RECT 127.575 -159.305 128.040 -140.070 ;
        RECT 128.340 -159.305 128.805 -140.070 ;
        RECT 129.105 -159.305 129.570 -140.070 ;
        RECT 129.870 -159.305 130.335 -140.070 ;
        RECT 130.635 -159.305 131.100 -140.070 ;
        RECT 131.400 -159.305 131.865 -140.070 ;
        RECT 132.165 -159.305 132.630 -140.070 ;
        RECT 132.930 -159.305 133.395 -140.070 ;
        RECT 133.695 -159.305 134.160 -140.070 ;
        RECT 134.460 -159.305 134.925 -140.070 ;
        RECT 135.225 -159.305 135.690 -140.070 ;
        RECT 135.990 -159.305 136.455 -140.070 ;
        RECT 136.755 -159.305 137.220 -140.070 ;
        RECT 137.520 -159.305 137.985 -140.070 ;
        RECT 138.285 -159.305 138.750 -140.070 ;
        RECT 139.050 -159.305 139.515 -140.070 ;
        RECT 139.815 -144.275 140.280 -140.070 ;
        RECT 140.580 -144.275 141.045 -140.070 ;
        RECT 141.345 -144.275 141.810 -140.070 ;
        RECT 142.110 -159.305 142.575 -140.070 ;
        RECT 142.875 -159.305 143.340 -140.070 ;
        RECT 143.640 -159.305 144.105 -140.070 ;
        RECT 144.405 -159.305 144.870 -140.070 ;
        RECT 145.170 -159.305 145.635 -140.070 ;
        RECT 145.935 -159.305 146.400 -140.070 ;
        RECT 146.700 -159.305 147.165 -140.070 ;
        RECT 147.465 -159.305 147.930 -140.070 ;
        RECT 148.230 -159.305 148.695 -140.070 ;
        RECT 148.995 -159.305 149.460 -140.070 ;
        RECT 149.760 -159.305 150.225 -140.070 ;
        RECT 150.525 -159.305 150.990 -140.070 ;
        RECT 151.290 -159.305 151.755 -140.070 ;
        RECT 152.055 -159.305 152.520 -140.070 ;
        RECT 152.820 -159.305 153.285 -140.070 ;
        RECT 153.585 -159.305 154.050 -140.070 ;
        RECT 154.350 -159.305 154.815 -140.070 ;
        RECT 155.115 -159.305 155.580 -140.070 ;
        RECT 155.880 -159.305 156.345 -140.070 ;
        RECT 156.645 -159.305 157.110 -140.070 ;
        RECT 157.410 -159.305 157.875 -140.070 ;
        RECT 158.175 -159.305 158.640 -140.070 ;
        RECT 158.940 -159.305 159.405 -140.070 ;
        RECT 159.705 -159.505 160.170 -140.070 ;
        RECT 160.470 -159.505 160.935 -140.070 ;
        RECT 161.235 -159.505 161.700 -140.070 ;
        RECT 162.000 -159.505 162.825 -140.070 ;
        RECT 122.220 -171.740 122.685 -165.540 ;
        RECT 122.985 -171.740 123.450 -165.610 ;
        RECT 123.750 -171.740 124.215 -165.610 ;
        RECT 125.490 -171.740 125.955 -165.610 ;
        RECT 126.255 -171.740 126.720 -165.610 ;
        RECT 127.020 -171.740 127.485 -165.610 ;
        RECT 127.785 -171.740 128.250 -165.610 ;
        RECT 129.360 -171.740 129.825 -165.610 ;
        RECT 130.125 -171.740 130.590 -165.610 ;
        RECT 130.890 -171.740 131.355 -165.610 ;
        RECT 131.655 -171.740 132.120 -165.610 ;
        RECT 132.420 -171.740 132.885 -165.610 ;
        RECT 133.185 -171.740 133.650 -167.860 ;
        RECT 133.950 -171.740 134.415 -167.860 ;
        RECT 134.715 -171.740 135.180 -165.610 ;
        RECT 135.480 -171.740 135.945 -165.610 ;
        RECT 136.245 -171.740 136.710 -165.610 ;
        RECT 137.010 -171.740 137.475 -165.610 ;
        RECT 137.775 -171.740 138.240 -165.610 ;
        RECT 162.360 -188.260 162.825 -159.505 ;
        RECT 163.125 -188.260 163.590 -140.070 ;
        RECT 166.185 -188.260 166.650 -140.070 ;
        RECT 168.480 -188.260 168.945 -140.070 ;
        RECT 169.245 -188.260 169.710 -140.070 ;
        RECT 170.010 -188.260 170.475 -140.070 ;
        RECT 170.775 -188.260 171.240 -140.070 ;
        RECT 171.540 -188.260 172.005 -140.070 ;
        RECT 172.305 -171.320 172.780 -140.070 ;
        RECT 173.080 -171.325 173.555 -140.070 ;
        RECT 173.855 -171.325 174.330 -140.070 ;
        RECT 174.630 -171.325 175.105 -140.070 ;
        RECT 175.410 -171.325 175.990 -140.070 ;
        RECT 176.430 -188.260 176.895 -140.070 ;
        RECT 177.195 -188.260 177.660 -140.070 ;
        RECT 177.960 -188.260 178.425 -140.070 ;
        RECT 178.725 -188.260 179.190 -140.070 ;
        RECT 179.490 -188.260 179.955 -140.070 ;
        RECT 180.255 -188.260 180.720 -140.070 ;
        RECT 181.020 -188.260 181.485 -140.070 ;
        RECT 181.785 -188.260 182.250 -140.070 ;
        RECT 182.550 -188.260 183.015 -140.070 ;
        RECT 183.315 -188.260 183.780 -140.070 ;
        RECT 184.080 -171.335 184.545 -140.070 ;
        RECT 184.845 -171.335 185.310 -140.070 ;
        RECT 185.610 -171.335 186.075 -140.070 ;
        RECT 186.375 -171.335 186.840 -140.070 ;
        RECT 187.140 -171.335 187.605 -140.070 ;
        RECT 187.905 -171.335 188.370 -140.070 ;
        RECT 188.690 -188.260 189.155 -140.070 ;
        RECT 189.455 -188.260 189.920 -140.070 ;
        RECT 190.220 -188.260 190.685 -140.070 ;
        RECT 190.985 -188.260 191.450 -140.070 ;
        RECT 191.750 -188.260 192.215 -140.070 ;
        RECT 194.420 -188.260 194.885 -140.070 ;
        RECT 196.790 -188.260 197.255 -140.070 ;
        RECT 197.555 -188.260 198.500 -140.070 ;
    END
  END VDD
  PIN GND
    ANTENNAGATEAREA 40.189999 ;
    ANTENNADIFFAREA 44.552898 ;
    PORT
      LAYER pwell ;
        RECT 122.280 -160.050 159.640 -159.620 ;
        RECT 122.280 -164.870 122.710 -160.050 ;
        RECT 131.160 -164.870 131.590 -160.050 ;
        RECT 147.770 -164.870 148.200 -160.050 ;
        RECT 159.210 -164.870 159.640 -160.050 ;
        RECT 122.280 -165.300 159.640 -164.870 ;
        RECT 122.440 -178.350 137.920 -172.255 ;
        RECT 122.440 -178.440 123.580 -178.350 ;
        RECT 135.130 -178.440 137.920 -178.350 ;
        RECT 122.400 -180.450 129.970 -178.440 ;
        RECT 130.525 -180.450 138.095 -178.440 ;
      LAYER li1 ;
        RECT 122.410 -159.920 159.510 -159.750 ;
        RECT 122.410 -165.000 122.580 -159.920 ;
        RECT 122.970 -160.260 123.140 -159.920 ;
        RECT 124.260 -160.260 124.430 -159.920 ;
        RECT 125.550 -160.260 125.720 -159.920 ;
        RECT 126.840 -160.260 127.010 -159.920 ;
        RECT 128.130 -160.260 128.300 -159.920 ;
        RECT 129.420 -160.260 129.590 -159.920 ;
        RECT 130.710 -160.260 130.880 -159.920 ;
        RECT 122.970 -160.430 130.880 -160.260 ;
        RECT 122.970 -161.310 123.140 -160.430 ;
        RECT 124.260 -161.310 124.430 -160.430 ;
        RECT 125.550 -161.310 125.720 -160.430 ;
        RECT 126.840 -161.310 127.010 -160.430 ;
        RECT 128.130 -161.310 128.300 -160.430 ;
        RECT 129.420 -161.310 129.590 -160.430 ;
        RECT 130.710 -161.310 130.880 -160.430 ;
        RECT 122.970 -161.480 130.880 -161.310 ;
        RECT 122.970 -163.610 130.880 -163.440 ;
        RECT 122.970 -164.490 123.140 -163.610 ;
        RECT 124.260 -164.490 124.430 -163.610 ;
        RECT 125.550 -164.490 125.720 -163.610 ;
        RECT 126.840 -164.490 127.010 -163.610 ;
        RECT 128.130 -164.490 128.300 -163.610 ;
        RECT 129.420 -164.490 129.590 -163.610 ;
        RECT 130.710 -164.490 130.880 -163.610 ;
        RECT 122.970 -164.660 130.880 -164.490 ;
        RECT 122.970 -165.000 123.140 -164.660 ;
        RECT 124.260 -165.000 124.430 -164.660 ;
        RECT 125.550 -165.000 125.720 -164.660 ;
        RECT 126.840 -165.000 127.010 -164.660 ;
        RECT 128.130 -165.000 128.300 -164.660 ;
        RECT 129.420 -165.000 129.590 -164.660 ;
        RECT 131.290 -165.000 131.460 -159.920 ;
        RECT 131.840 -160.260 132.010 -159.920 ;
        RECT 133.130 -160.260 133.300 -159.920 ;
        RECT 134.420 -160.260 134.590 -159.920 ;
        RECT 135.710 -160.260 135.880 -159.920 ;
        RECT 137.000 -160.260 137.170 -159.920 ;
        RECT 138.290 -160.260 138.460 -159.920 ;
        RECT 140.870 -160.260 141.040 -159.920 ;
        RECT 142.160 -160.260 142.330 -159.920 ;
        RECT 143.450 -160.260 143.620 -159.920 ;
        RECT 144.740 -160.260 144.910 -159.920 ;
        RECT 146.030 -160.260 146.200 -159.920 ;
        RECT 147.320 -160.260 147.490 -159.920 ;
        RECT 131.840 -160.430 147.490 -160.260 ;
        RECT 131.840 -161.310 132.010 -160.430 ;
        RECT 133.130 -161.310 133.300 -160.430 ;
        RECT 134.420 -161.310 134.590 -160.430 ;
        RECT 135.710 -161.310 135.880 -160.430 ;
        RECT 137.000 -161.310 137.170 -160.430 ;
        RECT 138.290 -161.310 138.460 -160.430 ;
        RECT 139.580 -161.310 139.750 -160.430 ;
        RECT 140.870 -161.310 141.040 -160.430 ;
        RECT 142.160 -161.310 142.330 -160.430 ;
        RECT 143.450 -161.310 143.620 -160.430 ;
        RECT 144.740 -161.310 144.910 -160.430 ;
        RECT 146.030 -161.310 146.200 -160.430 ;
        RECT 147.320 -161.310 147.490 -160.430 ;
        RECT 131.840 -161.480 147.490 -161.310 ;
        RECT 132.175 -162.020 132.965 -161.850 ;
        RECT 146.365 -162.020 147.155 -161.850 ;
        RECT 131.840 -162.730 132.010 -162.190 ;
        RECT 133.130 -162.730 133.300 -162.190 ;
        RECT 135.710 -162.730 135.880 -162.190 ;
        RECT 138.290 -162.730 138.460 -162.190 ;
        RECT 140.870 -162.730 141.040 -162.190 ;
        RECT 143.450 -162.730 143.620 -162.190 ;
        RECT 146.030 -162.730 146.200 -162.190 ;
        RECT 147.320 -162.730 147.490 -162.190 ;
        RECT 132.175 -163.070 132.965 -162.900 ;
        RECT 146.365 -163.070 147.155 -162.900 ;
        RECT 131.840 -163.610 147.490 -163.440 ;
        RECT 131.840 -164.490 132.010 -163.610 ;
        RECT 133.130 -164.490 133.300 -163.610 ;
        RECT 134.420 -164.490 134.590 -163.610 ;
        RECT 135.710 -164.490 135.880 -163.610 ;
        RECT 137.000 -164.490 137.170 -163.610 ;
        RECT 138.290 -164.490 138.460 -163.610 ;
        RECT 139.580 -164.490 139.750 -163.610 ;
        RECT 140.870 -164.490 141.040 -163.610 ;
        RECT 142.160 -164.490 142.330 -163.610 ;
        RECT 143.450 -164.490 143.620 -163.610 ;
        RECT 144.740 -164.490 144.910 -163.610 ;
        RECT 146.030 -164.490 146.200 -163.610 ;
        RECT 147.320 -164.490 147.490 -163.610 ;
        RECT 131.840 -164.660 147.490 -164.490 ;
        RECT 131.840 -165.000 132.010 -164.660 ;
        RECT 133.130 -165.000 133.300 -164.660 ;
        RECT 134.420 -165.000 134.590 -164.660 ;
        RECT 135.710 -165.000 135.880 -164.660 ;
        RECT 137.000 -165.000 137.170 -164.660 ;
        RECT 138.290 -165.000 138.460 -164.660 ;
        RECT 139.580 -165.000 139.750 -164.660 ;
        RECT 140.870 -165.000 141.040 -164.660 ;
        RECT 142.160 -165.000 142.330 -164.660 ;
        RECT 143.450 -165.000 143.620 -164.660 ;
        RECT 144.740 -165.000 144.910 -164.660 ;
        RECT 146.030 -165.000 146.200 -164.660 ;
        RECT 147.320 -165.000 147.490 -164.660 ;
        RECT 147.900 -165.000 148.070 -159.920 ;
        RECT 148.440 -160.260 148.610 -159.920 ;
        RECT 149.730 -160.260 149.900 -159.920 ;
        RECT 151.020 -160.260 151.190 -159.920 ;
        RECT 152.310 -160.260 152.480 -159.920 ;
        RECT 153.600 -160.260 153.770 -159.920 ;
        RECT 154.890 -160.260 155.060 -159.920 ;
        RECT 156.180 -160.260 156.350 -159.920 ;
        RECT 157.470 -160.260 157.640 -159.920 ;
        RECT 158.760 -160.260 158.930 -159.920 ;
        RECT 148.440 -160.430 158.930 -160.260 ;
        RECT 148.440 -161.310 148.610 -160.430 ;
        RECT 149.730 -161.310 149.900 -160.430 ;
        RECT 151.020 -161.310 151.190 -160.430 ;
        RECT 152.310 -161.310 152.480 -160.430 ;
        RECT 153.600 -161.310 153.770 -160.430 ;
        RECT 154.890 -161.310 155.060 -160.430 ;
        RECT 156.180 -161.310 156.350 -160.430 ;
        RECT 157.470 -161.310 157.640 -160.430 ;
        RECT 158.760 -161.310 158.930 -160.430 ;
        RECT 148.440 -161.480 158.930 -161.310 ;
        RECT 148.775 -162.020 149.565 -161.850 ;
        RECT 157.805 -162.020 158.595 -161.850 ;
        RECT 148.440 -162.730 148.610 -162.190 ;
        RECT 149.730 -162.730 149.900 -162.190 ;
        RECT 152.310 -162.730 152.480 -162.190 ;
        RECT 154.890 -162.730 155.060 -162.190 ;
        RECT 157.470 -162.730 157.640 -162.190 ;
        RECT 158.760 -162.730 158.930 -162.190 ;
        RECT 148.775 -163.070 149.565 -162.900 ;
        RECT 157.805 -163.070 158.595 -162.900 ;
        RECT 148.440 -163.610 158.930 -163.440 ;
        RECT 148.440 -164.490 148.610 -163.610 ;
        RECT 149.730 -164.490 149.900 -163.610 ;
        RECT 151.020 -164.490 151.190 -163.610 ;
        RECT 152.310 -164.490 152.480 -163.610 ;
        RECT 153.600 -164.490 153.770 -163.610 ;
        RECT 154.890 -164.490 155.060 -163.610 ;
        RECT 156.180 -164.490 156.350 -163.610 ;
        RECT 157.470 -164.490 157.640 -163.610 ;
        RECT 158.760 -164.490 158.930 -163.610 ;
        RECT 148.440 -164.660 158.930 -164.490 ;
        RECT 148.440 -165.000 148.610 -164.660 ;
        RECT 149.730 -165.000 149.900 -164.660 ;
        RECT 151.020 -165.000 151.190 -164.660 ;
        RECT 152.310 -165.000 152.480 -164.660 ;
        RECT 153.600 -165.000 153.770 -164.660 ;
        RECT 154.890 -165.000 155.060 -164.660 ;
        RECT 156.180 -165.000 156.350 -164.660 ;
        RECT 157.470 -165.000 157.640 -164.660 ;
        RECT 158.760 -165.000 158.930 -164.660 ;
        RECT 159.340 -165.000 159.510 -159.920 ;
        RECT 122.410 -165.170 159.510 -165.000 ;
        RECT 122.580 -172.555 137.915 -172.385 ;
        RECT 122.580 -178.155 122.750 -172.555 ;
        RECT 123.495 -173.070 127.195 -172.900 ;
        RECT 123.155 -173.950 123.325 -173.240 ;
        RECT 124.445 -173.950 124.615 -173.240 ;
        RECT 125.735 -174.120 125.905 -173.070 ;
        RECT 127.025 -174.120 127.195 -173.070 ;
        RECT 123.495 -174.290 127.195 -174.120 ;
        RECT 127.585 -173.150 135.715 -172.980 ;
        RECT 136.225 -173.150 137.005 -172.980 ;
        RECT 127.585 -174.030 127.755 -173.150 ;
        RECT 128.875 -174.030 129.045 -173.150 ;
        RECT 130.165 -174.030 130.335 -173.150 ;
        RECT 131.455 -174.030 131.625 -173.150 ;
        RECT 132.745 -174.030 132.915 -173.150 ;
        RECT 133.305 -174.030 133.475 -173.150 ;
        RECT 134.595 -174.030 134.765 -173.150 ;
        RECT 135.885 -173.860 136.055 -173.320 ;
        RECT 137.175 -173.860 137.345 -173.320 ;
        RECT 127.585 -174.200 135.715 -174.030 ;
        RECT 136.225 -174.200 137.005 -174.030 ;
        RECT 123.495 -174.830 124.275 -174.660 ;
        RECT 136.225 -174.910 137.005 -174.740 ;
        RECT 123.155 -175.710 123.325 -175.000 ;
        RECT 124.445 -175.710 124.615 -175.000 ;
        RECT 128.875 -175.620 129.045 -175.080 ;
        RECT 131.455 -175.620 131.625 -175.080 ;
        RECT 135.885 -175.620 136.055 -175.080 ;
        RECT 137.175 -175.620 137.345 -175.080 ;
        RECT 123.495 -176.050 124.275 -175.880 ;
        RECT 136.225 -175.960 137.005 -175.790 ;
        RECT 123.495 -176.590 127.195 -176.420 ;
        RECT 123.155 -177.470 123.325 -176.760 ;
        RECT 124.445 -177.470 124.615 -176.760 ;
        RECT 125.735 -177.640 125.905 -176.590 ;
        RECT 127.025 -177.640 127.195 -176.590 ;
        RECT 123.495 -177.810 127.195 -177.640 ;
        RECT 127.585 -176.670 135.715 -176.500 ;
        RECT 136.195 -176.670 137.035 -176.500 ;
        RECT 127.585 -177.550 127.755 -176.670 ;
        RECT 128.875 -177.550 129.045 -176.670 ;
        RECT 130.165 -177.550 130.335 -176.670 ;
        RECT 131.455 -177.550 131.625 -176.670 ;
        RECT 132.745 -177.550 132.915 -176.670 ;
        RECT 133.305 -177.550 133.475 -176.670 ;
        RECT 134.595 -177.550 134.765 -176.670 ;
        RECT 135.885 -177.380 136.055 -176.840 ;
        RECT 137.175 -177.380 137.345 -176.840 ;
        RECT 127.585 -177.720 135.715 -177.550 ;
        RECT 136.195 -177.720 137.035 -177.550 ;
        RECT 137.745 -178.155 137.915 -172.555 ;
        RECT 122.580 -178.625 137.915 -178.155 ;
        RECT 122.580 -178.790 129.790 -178.625 ;
        RECT 122.580 -180.100 122.750 -178.790 ;
        RECT 129.620 -180.100 129.790 -178.790 ;
        RECT 122.580 -180.270 129.790 -180.100 ;
        RECT 130.705 -178.790 137.915 -178.625 ;
        RECT 130.705 -180.100 130.875 -178.790 ;
        RECT 137.745 -180.100 137.915 -178.790 ;
        RECT 130.705 -180.270 137.915 -180.100 ;
      LAYER met1 ;
        RECT 125.475 -159.675 125.795 -159.670 ;
        RECT 122.295 -164.915 122.655 -159.675 ;
        RECT 124.605 -159.980 126.670 -159.675 ;
        RECT 127.180 -159.980 129.255 -159.675 ;
        RECT 129.925 -159.980 139.165 -159.675 ;
        RECT 140.075 -159.970 149.975 -159.675 ;
        RECT 125.475 -159.990 125.795 -159.980 ;
        RECT 128.055 -159.995 128.375 -159.980 ;
        RECT 131.205 -160.070 131.525 -159.980 ;
        RECT 122.940 -163.640 124.460 -163.410 ;
        RECT 122.940 -164.460 123.170 -163.640 ;
        RECT 124.230 -164.460 124.460 -163.640 ;
        RECT 122.940 -164.690 124.460 -164.460 ;
        RECT 122.940 -164.915 123.170 -164.690 ;
        RECT 124.230 -164.915 124.460 -164.690 ;
        RECT 126.810 -164.915 127.040 -162.885 ;
        RECT 129.390 -163.640 130.910 -163.410 ;
        RECT 129.390 -164.460 129.620 -163.640 ;
        RECT 130.680 -164.460 130.910 -163.640 ;
        RECT 129.390 -164.690 130.910 -164.460 ;
        RECT 131.260 -164.600 131.490 -160.070 ;
        RECT 131.765 -160.230 132.085 -159.980 ;
        RECT 133.055 -160.230 133.375 -159.980 ;
        RECT 135.635 -160.230 135.955 -159.980 ;
        RECT 138.215 -160.230 138.535 -159.980 ;
        RECT 140.800 -160.230 141.120 -159.970 ;
        RECT 143.375 -160.230 143.695 -159.970 ;
        RECT 145.955 -160.230 146.275 -159.970 ;
        RECT 147.245 -160.230 147.565 -159.970 ;
        RECT 131.765 -160.315 139.395 -160.230 ;
        RECT 131.810 -160.460 139.395 -160.315 ;
        RECT 139.935 -160.315 147.565 -160.230 ;
        RECT 139.935 -160.460 147.520 -160.315 ;
        RECT 131.810 -161.280 132.040 -160.460 ;
        RECT 133.100 -161.280 133.330 -160.460 ;
        RECT 134.390 -161.280 134.620 -160.460 ;
        RECT 135.680 -161.280 135.910 -160.460 ;
        RECT 136.970 -161.280 137.200 -160.460 ;
        RECT 138.260 -161.280 138.490 -160.460 ;
        RECT 140.840 -161.280 141.070 -160.460 ;
        RECT 142.130 -161.280 142.360 -160.460 ;
        RECT 143.420 -161.280 143.650 -160.460 ;
        RECT 144.710 -161.280 144.940 -160.460 ;
        RECT 146.000 -161.280 146.230 -160.460 ;
        RECT 147.290 -161.280 147.520 -160.460 ;
        RECT 131.810 -161.510 139.415 -161.280 ;
        RECT 139.935 -161.510 147.520 -161.280 ;
        RECT 131.810 -161.820 132.040 -161.510 ;
        RECT 133.100 -161.820 133.330 -161.510 ;
        RECT 131.810 -162.050 133.330 -161.820 ;
        RECT 131.810 -162.870 132.040 -162.050 ;
        RECT 133.100 -162.870 133.330 -162.050 ;
        RECT 131.810 -163.100 133.330 -162.870 ;
        RECT 131.810 -163.410 132.040 -163.100 ;
        RECT 133.100 -163.410 133.330 -163.100 ;
        RECT 131.810 -163.640 133.330 -163.410 ;
        RECT 131.810 -164.460 132.040 -163.640 ;
        RECT 133.100 -164.460 133.330 -163.640 ;
        RECT 131.810 -164.600 133.330 -164.460 ;
        RECT 135.680 -164.600 135.910 -161.510 ;
        RECT 138.260 -164.600 138.490 -161.510 ;
        RECT 140.840 -164.600 141.070 -161.510 ;
        RECT 143.420 -164.600 143.650 -161.510 ;
        RECT 146.000 -161.820 146.230 -161.510 ;
        RECT 147.290 -161.820 147.520 -161.510 ;
        RECT 146.000 -162.050 147.520 -161.820 ;
        RECT 146.000 -162.870 146.230 -162.050 ;
        RECT 147.290 -162.870 147.520 -162.050 ;
        RECT 146.000 -163.100 147.520 -162.870 ;
        RECT 146.000 -163.410 146.230 -163.100 ;
        RECT 147.290 -163.410 147.520 -163.100 ;
        RECT 146.000 -163.640 147.520 -163.410 ;
        RECT 146.000 -164.460 146.230 -163.640 ;
        RECT 147.290 -164.460 147.520 -163.640 ;
        RECT 146.000 -164.600 147.520 -164.460 ;
        RECT 129.390 -164.915 129.620 -164.690 ;
        RECT 130.680 -164.915 130.910 -164.690 ;
        RECT 131.205 -164.915 131.525 -164.600 ;
        RECT 131.755 -164.690 133.365 -164.600 ;
        RECT 131.755 -164.915 132.075 -164.690 ;
        RECT 133.045 -164.915 133.365 -164.690 ;
        RECT 135.625 -164.915 135.945 -164.600 ;
        RECT 138.205 -164.915 138.525 -164.600 ;
        RECT 140.790 -164.915 141.110 -164.600 ;
        RECT 143.370 -164.915 143.690 -164.600 ;
        RECT 145.950 -164.690 147.560 -164.600 ;
        RECT 145.950 -164.915 146.270 -164.690 ;
        RECT 147.240 -164.915 147.560 -164.690 ;
        RECT 147.870 -164.915 148.100 -159.970 ;
        RECT 148.365 -160.230 148.685 -159.970 ;
        RECT 149.655 -160.230 149.975 -159.970 ;
        RECT 151.370 -159.975 153.420 -159.675 ;
        RECT 153.960 -159.975 156.010 -159.675 ;
        RECT 156.550 -159.970 159.605 -159.670 ;
        RECT 148.365 -160.315 149.975 -160.230 ;
        RECT 152.235 -160.315 152.555 -159.975 ;
        RECT 154.820 -160.315 155.140 -159.975 ;
        RECT 157.395 -160.175 157.715 -159.970 ;
        RECT 158.680 -160.175 159.000 -159.970 ;
        RECT 157.395 -160.315 159.000 -160.175 ;
        RECT 148.410 -160.460 149.930 -160.315 ;
        RECT 148.410 -161.280 148.640 -160.460 ;
        RECT 149.700 -161.280 149.930 -160.460 ;
        RECT 148.410 -161.510 149.930 -161.280 ;
        RECT 148.410 -161.820 148.640 -161.510 ;
        RECT 149.700 -161.820 149.930 -161.510 ;
        RECT 148.410 -162.050 149.930 -161.820 ;
        RECT 148.410 -162.870 148.640 -162.050 ;
        RECT 149.700 -162.870 149.930 -162.050 ;
        RECT 148.410 -163.100 149.930 -162.870 ;
        RECT 148.410 -163.410 148.640 -163.100 ;
        RECT 149.700 -163.410 149.930 -163.100 ;
        RECT 148.410 -163.640 149.930 -163.410 ;
        RECT 148.410 -164.460 148.640 -163.640 ;
        RECT 149.700 -164.460 149.930 -163.640 ;
        RECT 148.410 -164.600 149.930 -164.460 ;
        RECT 152.280 -164.600 152.510 -160.315 ;
        RECT 154.860 -164.600 155.090 -160.315 ;
        RECT 157.440 -160.460 158.960 -160.315 ;
        RECT 157.440 -161.280 157.670 -160.460 ;
        RECT 158.730 -161.280 158.960 -160.460 ;
        RECT 157.440 -161.510 158.960 -161.280 ;
        RECT 157.440 -161.820 157.670 -161.510 ;
        RECT 158.730 -161.820 158.960 -161.510 ;
        RECT 157.440 -162.050 158.960 -161.820 ;
        RECT 157.440 -162.870 157.670 -162.050 ;
        RECT 158.730 -162.870 158.960 -162.050 ;
        RECT 157.440 -163.100 158.960 -162.870 ;
        RECT 157.440 -163.410 157.670 -163.100 ;
        RECT 158.730 -163.410 158.960 -163.100 ;
        RECT 157.440 -163.640 158.960 -163.410 ;
        RECT 157.440 -164.460 157.670 -163.640 ;
        RECT 158.730 -164.460 158.960 -163.640 ;
        RECT 157.440 -164.600 158.960 -164.460 ;
        RECT 148.365 -164.690 149.970 -164.600 ;
        RECT 148.365 -164.915 148.685 -164.690 ;
        RECT 149.650 -164.915 149.970 -164.690 ;
        RECT 152.230 -164.915 152.550 -164.600 ;
        RECT 154.810 -164.915 155.130 -164.600 ;
        RECT 157.395 -164.690 159.005 -164.600 ;
        RECT 157.395 -164.915 157.715 -164.690 ;
        RECT 158.685 -164.915 159.005 -164.690 ;
        RECT 122.295 -165.240 139.200 -164.915 ;
        RECT 140.005 -165.235 159.005 -164.915 ;
        RECT 159.245 -165.235 159.605 -159.970 ;
        RECT 140.790 -165.240 141.110 -165.235 ;
        RECT 138.260 -165.250 138.490 -165.240 ;
        RECT 122.495 -172.330 122.815 -172.275 ;
        RECT 122.495 -172.620 123.540 -172.330 ;
        RECT 124.185 -172.335 124.805 -172.325 ;
        RECT 124.175 -172.605 124.805 -172.335 ;
        RECT 128.785 -172.585 129.135 -172.325 ;
        RECT 124.185 -172.615 124.805 -172.605 ;
        RECT 122.495 -178.100 122.815 -172.620 ;
        RECT 123.125 -172.870 123.355 -172.620 ;
        RECT 124.415 -172.870 124.655 -172.615 ;
        RECT 123.125 -173.100 124.655 -172.870 ;
        RECT 123.125 -174.090 123.355 -173.100 ;
        RECT 124.415 -174.090 124.655 -173.100 ;
        RECT 123.125 -174.320 124.655 -174.090 ;
        RECT 123.125 -174.630 123.355 -174.320 ;
        RECT 124.415 -174.630 124.655 -174.320 ;
        RECT 123.125 -174.860 124.655 -174.630 ;
        RECT 123.125 -175.850 123.355 -174.860 ;
        RECT 124.415 -175.840 124.655 -174.860 ;
        RECT 124.415 -175.850 124.645 -175.840 ;
        RECT 123.125 -176.080 124.645 -175.850 ;
        RECT 123.125 -176.390 123.355 -176.080 ;
        RECT 124.415 -176.390 124.645 -176.080 ;
        RECT 123.125 -176.620 124.645 -176.390 ;
        RECT 123.125 -177.415 123.355 -176.620 ;
        RECT 123.065 -177.610 123.385 -177.415 ;
        RECT 124.415 -177.450 124.645 -176.620 ;
        RECT 128.845 -177.400 129.075 -172.585 ;
        RECT 131.230 -172.610 131.850 -172.320 ;
        RECT 131.425 -177.400 131.655 -172.610 ;
        RECT 135.660 -172.615 136.280 -172.325 ;
        RECT 136.940 -172.600 137.985 -172.310 ;
        RECT 135.825 -172.950 136.085 -172.615 ;
        RECT 137.145 -172.950 137.375 -172.600 ;
        RECT 134.950 -173.180 137.375 -172.950 ;
        RECT 135.825 -174.000 136.085 -173.180 ;
        RECT 137.145 -174.000 137.375 -173.180 ;
        RECT 134.950 -174.230 137.375 -174.000 ;
        RECT 135.825 -174.710 136.085 -174.230 ;
        RECT 137.145 -174.710 137.375 -174.230 ;
        RECT 135.825 -174.940 137.375 -174.710 ;
        RECT 135.825 -175.760 136.085 -174.940 ;
        RECT 137.145 -175.760 137.375 -174.940 ;
        RECT 135.825 -175.990 137.375 -175.760 ;
        RECT 135.825 -176.470 136.085 -175.990 ;
        RECT 137.145 -176.470 137.375 -175.990 ;
        RECT 134.950 -176.700 137.375 -176.470 ;
        RECT 135.825 -177.400 136.085 -176.700 ;
        RECT 137.145 -177.385 137.375 -176.700 ;
        RECT 124.370 -177.610 124.690 -177.450 ;
        RECT 123.065 -177.840 124.690 -177.610 ;
        RECT 128.810 -177.720 129.130 -177.400 ;
        RECT 123.065 -178.100 123.385 -177.840 ;
        RECT 124.370 -178.095 124.690 -177.840 ;
        RECT 122.495 -178.390 123.570 -178.100 ;
        RECT 124.225 -178.360 124.815 -178.095 ;
        RECT 128.805 -178.105 129.125 -177.720 ;
        RECT 131.380 -178.105 131.700 -177.400 ;
        RECT 135.795 -177.520 136.115 -177.400 ;
        RECT 137.100 -177.520 137.420 -177.385 ;
        RECT 134.950 -177.705 137.420 -177.520 ;
        RECT 134.950 -177.750 137.425 -177.705 ;
        RECT 135.795 -178.095 136.115 -177.750 ;
        RECT 137.105 -178.085 137.425 -177.750 ;
        RECT 137.665 -178.085 137.985 -172.600 ;
        RECT 128.655 -178.355 129.245 -178.105 ;
        RECT 131.245 -178.360 131.835 -178.105 ;
        RECT 135.655 -178.385 136.245 -178.095 ;
        RECT 136.945 -178.375 137.985 -178.085 ;
        RECT 142.600 -178.120 142.920 -165.235 ;
        RECT 143.370 -165.240 143.690 -165.235 ;
        RECT 145.950 -165.240 146.270 -165.235 ;
        RECT 147.240 -165.240 147.560 -165.235 ;
        RECT 148.365 -165.240 148.685 -165.235 ;
        RECT 149.650 -165.240 149.970 -165.235 ;
        RECT 152.230 -165.240 152.550 -165.235 ;
        RECT 154.810 -165.240 155.130 -165.235 ;
        RECT 157.395 -165.240 157.715 -165.235 ;
        RECT 158.685 -165.240 159.005 -165.235 ;
        RECT 122.495 -179.825 122.815 -178.390 ;
        RECT 137.665 -179.860 137.985 -178.375 ;
      LAYER met2 ;
        RECT 125.475 -159.675 125.795 -159.670 ;
        RECT 122.220 -160.315 190.970 -159.675 ;
        RECT 122.220 -165.240 190.885 -164.600 ;
        RECT 142.600 -171.280 197.960 -170.320 ;
        RECT 142.600 -171.290 149.300 -171.280 ;
        RECT 150.050 -171.290 197.960 -171.280 ;
        RECT 135.865 -176.520 198.680 -175.850 ;
        RECT 122.220 -178.120 198.680 -177.320 ;
      LAYER met3 ;
        RECT 122.220 -165.240 122.685 -159.610 ;
        RECT 122.985 -165.240 123.450 -159.610 ;
        RECT 123.750 -165.240 124.215 -159.610 ;
        RECT 124.515 -160.815 124.980 -159.610 ;
        RECT 125.490 -165.240 125.955 -159.610 ;
        RECT 126.255 -165.240 126.720 -159.610 ;
        RECT 127.020 -165.240 127.485 -159.610 ;
        RECT 127.785 -165.240 128.250 -159.610 ;
        RECT 128.550 -160.810 129.015 -159.610 ;
        RECT 129.360 -165.240 129.825 -159.610 ;
        RECT 130.125 -165.240 130.590 -159.610 ;
        RECT 130.890 -165.240 131.355 -159.610 ;
        RECT 131.655 -165.240 132.120 -159.610 ;
        RECT 132.420 -165.240 132.885 -159.610 ;
        RECT 133.540 -160.810 134.005 -159.610 ;
        RECT 134.715 -165.240 135.180 -159.610 ;
        RECT 135.480 -165.240 135.945 -159.610 ;
        RECT 136.245 -165.240 136.710 -159.610 ;
        RECT 137.010 -165.240 137.475 -159.610 ;
        RECT 137.775 -165.240 138.240 -159.610 ;
        RECT 138.540 -165.240 139.005 -159.610 ;
        RECT 139.305 -165.240 139.770 -159.610 ;
        RECT 142.105 -165.240 142.570 -159.610 ;
        RECT 142.870 -165.240 143.335 -159.610 ;
        RECT 143.635 -165.240 144.100 -159.610 ;
        RECT 144.400 -165.240 144.865 -159.610 ;
        RECT 145.180 -160.810 145.645 -159.610 ;
        RECT 145.950 -165.240 146.415 -159.610 ;
        RECT 146.715 -165.240 147.180 -159.610 ;
        RECT 147.480 -165.240 147.945 -159.610 ;
        RECT 148.245 -165.240 148.710 -159.610 ;
        RECT 149.010 -165.240 149.475 -159.610 ;
        RECT 149.775 -165.240 150.240 -159.610 ;
        RECT 150.540 -165.240 151.005 -159.610 ;
        RECT 151.305 -165.240 151.770 -159.610 ;
        RECT 152.070 -165.240 152.535 -159.610 ;
        RECT 152.835 -165.240 153.300 -159.610 ;
        RECT 153.600 -165.240 154.065 -159.610 ;
        RECT 154.365 -165.240 154.830 -159.610 ;
        RECT 155.130 -165.240 155.595 -159.610 ;
        RECT 155.895 -165.240 156.360 -159.610 ;
        RECT 156.660 -165.240 157.125 -159.610 ;
        RECT 157.425 -165.240 157.890 -159.610 ;
        RECT 158.190 -165.240 158.655 -159.610 ;
        RECT 158.955 -165.240 159.420 -159.610 ;
        RECT 122.220 -179.805 122.685 -172.375 ;
        RECT 122.985 -179.805 123.450 -172.375 ;
        RECT 123.750 -179.805 124.215 -172.375 ;
        RECT 124.610 -179.805 125.075 -173.875 ;
        RECT 125.490 -179.805 125.955 -172.375 ;
        RECT 126.255 -179.805 126.720 -172.375 ;
        RECT 127.020 -179.805 127.485 -172.375 ;
        RECT 127.785 -179.805 128.250 -172.375 ;
        RECT 128.550 -179.805 129.015 -173.875 ;
        RECT 129.360 -179.805 129.825 -172.375 ;
        RECT 130.125 -179.805 130.590 -172.375 ;
        RECT 130.890 -179.805 131.355 -172.375 ;
        RECT 131.655 -179.805 132.120 -172.375 ;
        RECT 132.420 -179.805 132.885 -172.375 ;
        RECT 133.185 -179.805 133.650 -172.375 ;
        RECT 133.950 -179.805 134.415 -172.375 ;
        RECT 134.715 -179.805 135.180 -172.375 ;
        RECT 135.480 -179.805 135.945 -172.375 ;
        RECT 136.245 -179.805 136.710 -172.375 ;
        RECT 137.010 -179.805 137.475 -172.375 ;
        RECT 137.775 -179.805 138.240 -172.375 ;
    END
  END GND
  PIN V_ldo
    ANTENNAGATEAREA 46.000000 ;
    ANTENNADIFFAREA 186.759995 ;
    PORT
      LAYER li1 ;
        RECT 196.805 -140.930 197.595 -140.760 ;
        RECT 158.300 -172.460 160.460 -172.110 ;
        RECT 165.510 -187.185 165.680 -141.145 ;
        RECT 168.090 -187.185 168.260 -141.145 ;
        RECT 170.670 -187.185 170.840 -141.145 ;
        RECT 173.250 -187.185 173.420 -141.145 ;
        RECT 175.830 -187.185 176.000 -141.145 ;
        RECT 178.410 -187.185 178.580 -141.145 ;
        RECT 180.990 -187.185 181.160 -141.145 ;
        RECT 183.570 -187.185 183.740 -141.145 ;
        RECT 186.150 -187.185 186.320 -141.145 ;
        RECT 188.730 -187.185 188.900 -141.145 ;
        RECT 191.310 -187.185 191.480 -141.145 ;
        RECT 193.890 -187.185 194.060 -141.145 ;
        RECT 196.470 -187.185 196.640 -141.145 ;
        RECT 197.760 -187.185 197.930 -141.145 ;
        RECT 196.805 -187.570 197.595 -187.400 ;
      LAYER met1 ;
        RECT 196.440 -140.960 197.960 -140.730 ;
        RECT 165.480 -171.650 165.710 -141.165 ;
        RECT 168.060 -171.650 168.290 -141.165 ;
        RECT 170.640 -171.650 170.870 -141.165 ;
        RECT 173.220 -171.650 173.450 -141.165 ;
        RECT 175.800 -171.650 176.030 -141.165 ;
        RECT 178.380 -171.650 178.610 -141.165 ;
        RECT 180.960 -171.650 181.190 -141.165 ;
        RECT 183.540 -171.650 183.770 -141.165 ;
        RECT 186.120 -171.650 186.350 -141.165 ;
        RECT 188.700 -171.650 188.930 -141.165 ;
        RECT 191.280 -171.650 191.510 -141.165 ;
        RECT 193.860 -171.650 194.090 -141.165 ;
        RECT 196.440 -171.650 196.670 -140.960 ;
        RECT 197.730 -171.650 197.960 -140.960 ;
        RECT 161.605 -172.160 161.925 -171.650 ;
        RECT 158.325 -172.410 161.925 -172.160 ;
        RECT 161.605 -172.930 161.925 -172.410 ;
        RECT 165.435 -172.930 165.755 -171.650 ;
        RECT 168.010 -172.930 168.330 -171.650 ;
        RECT 170.595 -172.930 170.915 -171.650 ;
        RECT 173.175 -172.930 173.495 -171.650 ;
        RECT 175.755 -172.930 176.075 -171.650 ;
        RECT 178.335 -172.930 178.655 -171.650 ;
        RECT 180.915 -172.930 181.235 -171.650 ;
        RECT 183.495 -172.930 183.815 -171.650 ;
        RECT 186.075 -172.930 186.395 -171.650 ;
        RECT 188.650 -172.930 188.970 -171.650 ;
        RECT 191.235 -172.930 191.555 -171.650 ;
        RECT 193.815 -172.930 194.135 -171.650 ;
        RECT 196.395 -172.930 196.715 -171.650 ;
        RECT 197.685 -172.930 198.005 -171.650 ;
        RECT 165.480 -187.165 165.710 -172.930 ;
        RECT 168.060 -174.235 168.290 -172.930 ;
        RECT 170.640 -174.235 170.870 -172.930 ;
        RECT 173.220 -174.235 173.450 -172.930 ;
        RECT 175.800 -174.235 176.030 -172.930 ;
        RECT 178.380 -174.235 178.610 -172.930 ;
        RECT 180.960 -174.235 181.190 -172.930 ;
        RECT 183.540 -174.225 183.770 -172.930 ;
        RECT 186.120 -174.225 186.350 -172.930 ;
        RECT 188.700 -174.225 188.930 -172.930 ;
        RECT 191.280 -174.225 191.510 -172.930 ;
        RECT 193.860 -174.225 194.090 -172.930 ;
        RECT 168.015 -175.530 168.335 -174.235 ;
        RECT 170.595 -175.530 170.915 -174.235 ;
        RECT 173.175 -175.530 173.495 -174.235 ;
        RECT 175.755 -175.530 176.075 -174.235 ;
        RECT 178.340 -175.530 178.660 -174.235 ;
        RECT 180.915 -175.530 181.235 -174.235 ;
        RECT 183.495 -175.520 183.815 -174.225 ;
        RECT 186.075 -175.520 186.395 -174.225 ;
        RECT 188.655 -175.520 188.975 -174.225 ;
        RECT 191.235 -175.520 191.555 -174.225 ;
        RECT 193.815 -175.520 194.135 -174.225 ;
        RECT 196.440 -174.235 196.670 -172.930 ;
        RECT 196.395 -175.520 196.715 -174.235 ;
        RECT 168.060 -187.165 168.290 -175.530 ;
        RECT 170.640 -187.165 170.870 -175.530 ;
        RECT 173.220 -187.165 173.450 -175.530 ;
        RECT 175.800 -187.165 176.030 -175.530 ;
        RECT 178.380 -187.165 178.610 -175.530 ;
        RECT 180.960 -187.165 181.190 -175.530 ;
        RECT 183.540 -187.165 183.770 -175.520 ;
        RECT 186.120 -187.165 186.350 -175.520 ;
        RECT 188.700 -187.165 188.930 -175.520 ;
        RECT 191.280 -187.165 191.510 -175.520 ;
        RECT 193.860 -187.165 194.090 -175.520 ;
        RECT 196.440 -187.365 196.670 -175.520 ;
        RECT 197.730 -187.365 197.960 -172.930 ;
        RECT 196.440 -187.595 197.960 -187.365 ;
        RECT 196.825 -187.600 197.575 -187.595 ;
      LAYER met2 ;
        RECT 161.480 -175.135 198.005 -171.650 ;
      LAYER met3 ;
        RECT 172.470 -234.070 174.150 -171.650 ;
        RECT 174.450 -234.070 176.130 -171.650 ;
        RECT 184.650 -174.240 186.335 -171.650 ;
        RECT 184.650 -234.065 186.330 -174.240 ;
        RECT 186.710 -234.070 188.390 -171.650 ;
      LAYER met4 ;
        RECT 128.395 -192.075 128.915 -191.080 ;
        RECT 145.455 -192.075 145.975 -191.080 ;
        RECT 162.515 -192.075 163.035 -191.080 ;
        RECT 121.850 -203.685 135.460 -192.075 ;
        RECT 138.910 -203.685 152.520 -192.075 ;
        RECT 155.970 -203.685 169.580 -192.075 ;
        RECT 128.395 -205.675 128.915 -203.685 ;
        RECT 145.455 -205.675 145.975 -203.685 ;
        RECT 162.515 -205.675 163.035 -203.685 ;
        RECT 121.850 -217.285 135.460 -205.675 ;
        RECT 138.910 -217.285 152.520 -205.675 ;
        RECT 155.970 -217.285 169.580 -205.675 ;
        RECT 128.395 -219.275 128.915 -217.285 ;
        RECT 145.455 -219.275 145.975 -217.285 ;
        RECT 162.515 -219.275 163.035 -217.285 ;
        RECT 121.850 -230.885 135.460 -219.275 ;
        RECT 138.910 -230.885 152.520 -219.275 ;
        RECT 155.970 -230.885 169.580 -219.275 ;
        RECT 128.395 -232.260 129.100 -230.885 ;
        RECT 145.370 -232.260 146.075 -230.885 ;
        RECT 162.270 -232.260 163.305 -230.885 ;
        RECT 128.335 -234.070 188.390 -232.260 ;
    END
  END V_ldo
  OBS
      LAYER pwell ;
        RECT 122.780 -161.250 131.070 -160.490 ;
        RECT 131.650 -161.250 147.680 -160.490 ;
        RECT 148.250 -161.250 159.120 -160.490 ;
        RECT 122.780 -162.840 131.070 -162.080 ;
        RECT 131.650 -162.840 147.680 -162.080 ;
        RECT 148.250 -162.840 159.120 -162.080 ;
        RECT 122.780 -164.430 131.070 -163.670 ;
        RECT 131.650 -164.430 147.680 -163.670 ;
        RECT 148.250 -164.430 159.120 -163.670 ;
        RECT 150.210 -170.450 160.410 -166.780 ;
        RECT 149.340 -174.120 161.290 -170.450 ;
        RECT 149.800 -177.790 160.870 -174.120 ;
      LAYER li1 ;
        RECT 164.555 -140.930 165.345 -140.760 ;
        RECT 165.845 -140.930 166.635 -140.760 ;
        RECT 167.135 -140.930 167.925 -140.760 ;
        RECT 168.425 -140.930 169.215 -140.760 ;
        RECT 169.715 -140.930 170.505 -140.760 ;
        RECT 171.005 -140.930 171.795 -140.760 ;
        RECT 172.295 -140.930 173.085 -140.760 ;
        RECT 173.585 -140.930 174.375 -140.760 ;
        RECT 174.875 -140.930 175.665 -140.760 ;
        RECT 176.165 -140.930 176.955 -140.760 ;
        RECT 177.455 -140.930 178.245 -140.760 ;
        RECT 178.745 -140.930 179.535 -140.760 ;
        RECT 180.035 -140.930 180.825 -140.760 ;
        RECT 181.325 -140.930 182.115 -140.760 ;
        RECT 182.615 -140.930 183.405 -140.760 ;
        RECT 183.905 -140.930 184.695 -140.760 ;
        RECT 185.195 -140.930 185.985 -140.760 ;
        RECT 186.485 -140.930 187.275 -140.760 ;
        RECT 187.775 -140.930 188.565 -140.760 ;
        RECT 189.065 -140.930 189.855 -140.760 ;
        RECT 190.355 -140.930 191.145 -140.760 ;
        RECT 191.645 -140.930 192.435 -140.760 ;
        RECT 192.935 -140.930 193.725 -140.760 ;
        RECT 194.225 -140.930 195.015 -140.760 ;
        RECT 195.515 -140.930 196.305 -140.760 ;
        RECT 123.200 -147.110 124.200 -146.940 ;
        RECT 124.595 -147.110 125.385 -146.940 ;
        RECT 125.885 -147.110 126.675 -146.940 ;
        RECT 127.175 -147.110 127.965 -146.940 ;
        RECT 128.465 -147.110 129.255 -146.940 ;
        RECT 129.650 -147.110 130.650 -146.940 ;
        RECT 133.475 -147.110 134.265 -146.940 ;
        RECT 134.765 -147.110 135.555 -146.940 ;
        RECT 136.055 -147.110 136.845 -146.940 ;
        RECT 137.345 -147.110 138.135 -146.940 ;
        RECT 138.635 -147.110 139.425 -146.940 ;
        RECT 139.925 -147.110 140.715 -146.940 ;
        RECT 141.215 -147.110 142.005 -146.940 ;
        RECT 142.505 -147.110 143.295 -146.940 ;
        RECT 143.795 -147.110 144.585 -146.940 ;
        RECT 145.085 -147.110 145.875 -146.940 ;
        RECT 146.375 -147.110 147.165 -146.940 ;
        RECT 147.665 -147.110 148.455 -146.940 ;
        RECT 152.655 -147.110 153.445 -146.940 ;
        RECT 153.945 -147.110 154.735 -146.940 ;
        RECT 155.235 -147.110 156.025 -146.940 ;
        RECT 156.525 -147.110 157.315 -146.940 ;
        RECT 157.815 -147.110 158.605 -146.940 ;
        RECT 159.105 -147.110 159.895 -146.940 ;
        RECT 122.970 -152.365 123.140 -147.325 ;
        RECT 124.260 -152.365 124.430 -147.325 ;
        RECT 126.840 -152.365 127.010 -147.325 ;
        RECT 129.420 -152.365 129.590 -147.325 ;
        RECT 130.710 -152.365 130.880 -147.325 ;
        RECT 134.430 -152.365 134.600 -147.325 ;
        RECT 137.010 -152.365 137.180 -147.325 ;
        RECT 139.590 -152.365 139.760 -147.325 ;
        RECT 142.170 -152.365 142.340 -147.325 ;
        RECT 144.750 -152.365 144.920 -147.325 ;
        RECT 147.330 -152.365 147.500 -147.325 ;
        RECT 153.610 -152.365 153.780 -147.325 ;
        RECT 156.190 -152.365 156.360 -147.325 ;
        RECT 158.770 -152.365 158.940 -147.325 ;
        RECT 123.200 -152.750 124.200 -152.580 ;
        RECT 124.595 -152.750 125.385 -152.580 ;
        RECT 125.885 -152.750 126.675 -152.580 ;
        RECT 127.175 -152.750 127.965 -152.580 ;
        RECT 128.465 -152.750 129.255 -152.580 ;
        RECT 129.650 -152.750 130.650 -152.580 ;
        RECT 133.475 -152.750 134.265 -152.580 ;
        RECT 134.765 -152.750 135.555 -152.580 ;
        RECT 136.055 -152.750 136.845 -152.580 ;
        RECT 137.345 -152.750 138.135 -152.580 ;
        RECT 138.635 -152.750 139.425 -152.580 ;
        RECT 139.925 -152.750 140.715 -152.580 ;
        RECT 141.215 -152.750 142.005 -152.580 ;
        RECT 142.505 -152.750 143.295 -152.580 ;
        RECT 143.795 -152.750 144.585 -152.580 ;
        RECT 145.085 -152.750 145.875 -152.580 ;
        RECT 146.375 -152.750 147.165 -152.580 ;
        RECT 147.665 -152.750 148.455 -152.580 ;
        RECT 152.655 -152.750 153.445 -152.580 ;
        RECT 153.945 -152.750 154.735 -152.580 ;
        RECT 155.235 -152.750 156.025 -152.580 ;
        RECT 156.525 -152.750 157.315 -152.580 ;
        RECT 157.815 -152.750 158.605 -152.580 ;
        RECT 159.105 -152.750 159.895 -152.580 ;
        RECT 123.305 -162.020 124.095 -161.850 ;
        RECT 124.595 -162.020 125.385 -161.850 ;
        RECT 128.465 -162.020 129.255 -161.850 ;
        RECT 129.755 -162.020 130.545 -161.850 ;
        RECT 133.465 -162.020 134.255 -161.850 ;
        RECT 134.755 -162.020 135.545 -161.850 ;
        RECT 136.045 -162.020 136.835 -161.850 ;
        RECT 137.335 -162.020 138.125 -161.850 ;
        RECT 138.625 -162.020 139.415 -161.850 ;
        RECT 139.915 -162.020 140.705 -161.850 ;
        RECT 141.205 -162.020 141.995 -161.850 ;
        RECT 142.495 -162.020 143.285 -161.850 ;
        RECT 143.785 -162.020 144.575 -161.850 ;
        RECT 145.075 -162.020 145.865 -161.850 ;
        RECT 150.065 -162.020 150.855 -161.850 ;
        RECT 151.355 -162.020 152.145 -161.850 ;
        RECT 152.645 -162.020 153.435 -161.850 ;
        RECT 153.935 -162.020 154.725 -161.850 ;
        RECT 155.225 -162.020 156.015 -161.850 ;
        RECT 156.515 -162.020 157.305 -161.850 ;
        RECT 122.970 -162.730 123.140 -162.190 ;
        RECT 124.260 -162.730 124.430 -162.190 ;
        RECT 125.550 -162.730 125.720 -162.190 ;
        RECT 126.840 -162.730 127.010 -162.190 ;
        RECT 128.130 -162.730 128.300 -162.190 ;
        RECT 129.420 -162.730 129.590 -162.190 ;
        RECT 130.710 -162.730 130.880 -162.190 ;
        RECT 134.420 -162.730 134.590 -162.190 ;
        RECT 137.000 -162.730 137.170 -162.190 ;
        RECT 139.580 -162.730 139.750 -162.190 ;
        RECT 142.160 -162.730 142.330 -162.190 ;
        RECT 144.740 -162.730 144.910 -162.190 ;
        RECT 151.020 -162.730 151.190 -162.190 ;
        RECT 153.600 -162.730 153.770 -162.190 ;
        RECT 156.180 -162.730 156.350 -162.190 ;
        RECT 123.305 -163.070 124.095 -162.900 ;
        RECT 124.595 -163.070 125.385 -162.900 ;
        RECT 128.465 -163.070 129.255 -162.900 ;
        RECT 129.755 -163.070 130.545 -162.900 ;
        RECT 133.465 -163.070 134.255 -162.900 ;
        RECT 134.755 -163.070 135.545 -162.900 ;
        RECT 136.045 -163.070 136.835 -162.900 ;
        RECT 137.335 -163.070 138.125 -162.900 ;
        RECT 138.625 -163.070 139.415 -162.900 ;
        RECT 139.915 -163.070 140.705 -162.900 ;
        RECT 141.205 -163.070 141.995 -162.900 ;
        RECT 142.495 -163.070 143.285 -162.900 ;
        RECT 143.785 -163.070 144.575 -162.900 ;
        RECT 145.075 -163.070 145.865 -162.900 ;
        RECT 150.065 -163.070 150.855 -162.900 ;
        RECT 151.355 -163.070 152.145 -162.900 ;
        RECT 152.645 -163.070 153.435 -162.900 ;
        RECT 153.935 -163.070 154.725 -162.900 ;
        RECT 155.225 -163.070 156.015 -162.900 ;
        RECT 156.515 -163.070 157.305 -162.900 ;
        RECT 129.425 -166.165 130.885 -165.995 ;
        RECT 129.425 -166.510 129.595 -166.165 ;
        RECT 124.015 -166.680 129.595 -166.510 ;
        RECT 123.705 -167.435 123.875 -166.895 ;
        RECT 124.995 -167.435 125.165 -166.895 ;
        RECT 126.285 -167.650 126.455 -166.680 ;
        RECT 127.575 -167.650 127.745 -166.680 ;
        RECT 128.865 -167.615 129.035 -166.680 ;
        RECT 129.425 -167.435 129.595 -166.680 ;
        RECT 130.715 -167.435 130.885 -166.165 ;
        RECT 129.425 -167.605 130.885 -167.435 ;
        RECT 150.390 -167.130 160.230 -166.960 ;
        RECT 129.425 -167.615 129.595 -167.605 ;
        RECT 128.525 -167.650 129.595 -167.615 ;
        RECT 124.015 -167.785 129.595 -167.650 ;
        RECT 124.015 -167.820 128.695 -167.785 ;
        RECT 129.765 -168.145 130.545 -167.975 ;
        RECT 133.125 -168.095 134.585 -168.060 ;
        RECT 124.015 -168.360 124.855 -168.190 ;
        RECT 125.335 -168.360 126.115 -168.190 ;
        RECT 126.625 -168.360 127.405 -168.190 ;
        RECT 127.575 -168.360 129.035 -168.190 ;
        RECT 131.615 -168.230 134.585 -168.095 ;
        RECT 134.755 -168.230 135.535 -168.060 ;
        RECT 131.615 -168.265 133.295 -168.230 ;
        RECT 123.705 -169.115 123.875 -168.575 ;
        RECT 124.995 -169.115 125.165 -168.575 ;
        RECT 127.575 -169.330 127.745 -168.360 ;
        RECT 128.865 -169.330 129.035 -168.360 ;
        RECT 129.425 -169.200 129.595 -168.360 ;
        RECT 132.565 -169.020 132.735 -168.480 ;
        RECT 133.125 -169.235 133.295 -168.265 ;
        RECT 124.015 -169.500 124.855 -169.330 ;
        RECT 125.335 -169.500 126.115 -169.330 ;
        RECT 126.625 -169.500 127.405 -169.330 ;
        RECT 127.575 -169.500 129.035 -169.330 ;
        RECT 131.615 -169.290 133.295 -169.235 ;
        RECT 134.415 -169.290 134.585 -168.230 ;
        RECT 131.615 -169.405 134.585 -169.290 ;
        RECT 129.765 -169.585 130.545 -169.415 ;
        RECT 133.125 -169.460 134.585 -169.405 ;
        RECT 134.755 -169.460 135.535 -169.290 ;
        RECT 124.015 -169.955 129.035 -169.870 ;
        RECT 124.015 -170.040 130.885 -169.955 ;
        RECT 123.705 -170.795 123.875 -170.255 ;
        RECT 124.995 -170.795 125.165 -170.255 ;
        RECT 126.285 -171.010 126.455 -170.040 ;
        RECT 127.575 -171.010 127.745 -170.040 ;
        RECT 128.865 -170.125 130.885 -170.040 ;
        RECT 128.865 -171.010 129.035 -170.125 ;
        RECT 129.425 -171.010 129.595 -170.125 ;
        RECT 124.015 -171.180 129.595 -171.010 ;
        RECT 129.425 -171.395 129.595 -171.180 ;
        RECT 130.715 -171.395 130.885 -170.125 ;
        RECT 150.390 -170.100 150.560 -167.130 ;
        RECT 151.040 -167.960 153.200 -167.610 ;
        RECT 157.420 -167.960 159.580 -167.610 ;
        RECT 151.040 -168.790 153.200 -168.440 ;
        RECT 157.420 -168.790 159.580 -168.440 ;
        RECT 151.040 -169.620 153.200 -169.270 ;
        RECT 157.420 -169.620 159.580 -169.270 ;
        RECT 160.060 -170.100 160.230 -167.130 ;
        RECT 150.390 -170.630 160.230 -170.100 ;
        RECT 129.425 -171.565 130.885 -171.395 ;
        RECT 149.520 -170.800 161.110 -170.630 ;
        RECT 149.520 -173.770 149.690 -170.800 ;
        RECT 150.170 -171.630 152.330 -171.280 ;
        RECT 158.300 -171.630 160.460 -171.280 ;
        RECT 150.170 -172.460 152.330 -172.110 ;
        RECT 150.170 -173.290 152.330 -172.940 ;
        RECT 158.300 -173.290 160.460 -172.940 ;
        RECT 160.940 -173.770 161.110 -170.800 ;
        RECT 149.520 -173.940 161.110 -173.770 ;
        RECT 149.980 -174.470 160.690 -173.940 ;
        RECT 124.785 -174.830 125.565 -174.660 ;
        RECT 126.045 -174.830 126.885 -174.660 ;
        RECT 127.925 -174.910 128.705 -174.740 ;
        RECT 129.215 -174.910 130.335 -174.740 ;
        RECT 130.505 -174.910 131.285 -174.740 ;
        RECT 131.795 -174.910 132.575 -174.740 ;
        RECT 133.305 -174.910 134.765 -174.740 ;
        RECT 134.935 -174.910 135.715 -174.740 ;
        RECT 125.735 -175.710 125.905 -175.000 ;
        RECT 127.025 -175.710 127.195 -175.000 ;
        RECT 127.585 -175.620 127.755 -175.080 ;
        RECT 130.165 -175.790 130.335 -174.910 ;
        RECT 132.745 -175.620 132.915 -175.080 ;
        RECT 133.305 -175.790 133.475 -174.910 ;
        RECT 134.595 -175.790 134.765 -174.910 ;
        RECT 124.785 -176.050 125.565 -175.880 ;
        RECT 126.045 -176.050 126.885 -175.880 ;
        RECT 127.925 -175.960 128.705 -175.790 ;
        RECT 129.215 -175.960 130.335 -175.790 ;
        RECT 130.505 -175.960 131.285 -175.790 ;
        RECT 131.795 -175.960 132.575 -175.790 ;
        RECT 133.305 -175.960 134.765 -175.790 ;
        RECT 134.935 -175.960 135.715 -175.790 ;
        RECT 149.980 -177.440 150.150 -174.470 ;
        RECT 150.630 -175.300 152.790 -174.950 ;
        RECT 157.880 -175.300 160.040 -174.950 ;
        RECT 160.520 -175.780 160.690 -174.470 ;
        RECT 150.630 -176.130 152.790 -175.780 ;
        RECT 157.880 -176.130 160.690 -175.780 ;
        RECT 150.630 -176.960 152.790 -176.610 ;
        RECT 157.880 -176.960 160.040 -176.610 ;
        RECT 160.520 -177.440 160.690 -176.130 ;
        RECT 149.980 -177.610 160.690 -177.440 ;
        RECT 123.230 -179.620 125.390 -179.270 ;
        RECT 126.980 -179.620 129.140 -179.270 ;
        RECT 131.355 -179.620 133.515 -179.270 ;
        RECT 135.105 -179.620 137.265 -179.270 ;
        RECT 164.555 -187.570 165.345 -187.400 ;
        RECT 165.845 -187.570 166.635 -187.400 ;
        RECT 167.135 -187.570 167.925 -187.400 ;
        RECT 168.425 -187.570 169.215 -187.400 ;
        RECT 169.715 -187.570 170.505 -187.400 ;
        RECT 171.005 -187.570 171.795 -187.400 ;
        RECT 172.295 -187.570 173.085 -187.400 ;
        RECT 173.585 -187.570 174.375 -187.400 ;
        RECT 174.875 -187.570 175.665 -187.400 ;
        RECT 176.165 -187.570 176.955 -187.400 ;
        RECT 177.455 -187.570 178.245 -187.400 ;
        RECT 178.745 -187.570 179.535 -187.400 ;
        RECT 180.035 -187.570 180.825 -187.400 ;
        RECT 181.325 -187.570 182.115 -187.400 ;
        RECT 182.615 -187.570 183.405 -187.400 ;
        RECT 183.905 -187.570 184.695 -187.400 ;
        RECT 185.195 -187.570 185.985 -187.400 ;
        RECT 186.485 -187.570 187.275 -187.400 ;
        RECT 187.775 -187.570 188.565 -187.400 ;
        RECT 189.065 -187.570 189.855 -187.400 ;
        RECT 190.355 -187.570 191.145 -187.400 ;
        RECT 191.645 -187.570 192.435 -187.400 ;
        RECT 192.935 -187.570 193.725 -187.400 ;
        RECT 194.225 -187.570 195.015 -187.400 ;
        RECT 195.515 -187.570 196.305 -187.400 ;
      LAYER met1 ;
        RECT 164.630 -140.730 165.270 -140.650 ;
        RECT 165.920 -140.730 166.560 -140.650 ;
        RECT 167.210 -140.730 167.850 -140.650 ;
        RECT 168.500 -140.730 169.140 -140.650 ;
        RECT 169.790 -140.730 170.430 -140.650 ;
        RECT 171.080 -140.730 171.720 -140.650 ;
        RECT 172.370 -140.730 173.010 -140.650 ;
        RECT 173.660 -140.730 174.300 -140.650 ;
        RECT 174.950 -140.730 175.590 -140.650 ;
        RECT 176.240 -140.730 176.880 -140.650 ;
        RECT 177.530 -140.730 178.170 -140.650 ;
        RECT 178.820 -140.730 179.460 -140.650 ;
        RECT 180.110 -140.730 180.750 -140.650 ;
        RECT 181.400 -140.730 182.040 -140.650 ;
        RECT 182.690 -140.730 183.330 -140.650 ;
        RECT 183.980 -140.730 184.620 -140.650 ;
        RECT 185.265 -140.730 185.905 -140.650 ;
        RECT 186.560 -140.730 187.200 -140.650 ;
        RECT 187.850 -140.730 188.490 -140.650 ;
        RECT 189.140 -140.730 189.780 -140.650 ;
        RECT 190.430 -140.730 191.070 -140.650 ;
        RECT 191.720 -140.730 192.360 -140.650 ;
        RECT 193.010 -140.730 193.650 -140.650 ;
        RECT 194.300 -140.730 194.940 -140.650 ;
        RECT 195.590 -140.730 196.230 -140.650 ;
        RECT 164.575 -140.960 165.325 -140.730 ;
        RECT 165.865 -140.960 166.615 -140.730 ;
        RECT 167.155 -140.960 167.905 -140.730 ;
        RECT 168.445 -140.960 169.195 -140.730 ;
        RECT 169.735 -140.960 170.485 -140.730 ;
        RECT 171.025 -140.960 171.775 -140.730 ;
        RECT 172.315 -140.960 173.065 -140.730 ;
        RECT 173.605 -140.960 174.355 -140.730 ;
        RECT 174.895 -140.960 175.645 -140.730 ;
        RECT 176.185 -140.960 176.935 -140.730 ;
        RECT 177.475 -140.960 178.225 -140.730 ;
        RECT 178.765 -140.960 179.515 -140.730 ;
        RECT 180.055 -140.960 180.805 -140.730 ;
        RECT 181.345 -140.960 182.095 -140.730 ;
        RECT 182.635 -140.960 183.385 -140.730 ;
        RECT 183.925 -140.960 184.675 -140.730 ;
        RECT 185.215 -140.960 185.965 -140.730 ;
        RECT 186.505 -140.960 187.255 -140.730 ;
        RECT 187.795 -140.960 188.545 -140.730 ;
        RECT 189.085 -140.960 189.835 -140.730 ;
        RECT 190.375 -140.960 191.125 -140.730 ;
        RECT 191.665 -140.960 192.415 -140.730 ;
        RECT 192.955 -140.960 193.705 -140.730 ;
        RECT 194.245 -140.960 194.995 -140.730 ;
        RECT 195.535 -140.960 196.285 -140.730 ;
        RECT 164.630 -140.970 165.270 -140.960 ;
        RECT 165.920 -140.970 166.560 -140.960 ;
        RECT 167.210 -140.970 167.850 -140.960 ;
        RECT 168.500 -140.970 169.140 -140.960 ;
        RECT 169.790 -140.970 170.430 -140.960 ;
        RECT 171.080 -140.970 171.720 -140.960 ;
        RECT 172.370 -140.970 173.010 -140.960 ;
        RECT 173.660 -140.970 174.300 -140.960 ;
        RECT 174.950 -140.970 175.590 -140.960 ;
        RECT 176.240 -140.970 176.880 -140.960 ;
        RECT 177.530 -140.970 178.170 -140.960 ;
        RECT 178.820 -140.970 179.460 -140.960 ;
        RECT 180.110 -140.970 180.750 -140.960 ;
        RECT 181.400 -140.970 182.040 -140.960 ;
        RECT 182.690 -140.970 183.330 -140.960 ;
        RECT 183.980 -140.970 184.620 -140.960 ;
        RECT 185.265 -140.970 185.905 -140.960 ;
        RECT 186.560 -140.970 187.200 -140.960 ;
        RECT 187.850 -140.970 188.490 -140.960 ;
        RECT 189.140 -140.970 189.780 -140.960 ;
        RECT 190.430 -140.970 191.070 -140.960 ;
        RECT 191.720 -140.970 192.360 -140.960 ;
        RECT 193.010 -140.970 193.650 -140.960 ;
        RECT 194.300 -140.970 194.940 -140.960 ;
        RECT 195.590 -140.970 196.230 -140.960 ;
        RECT 136.935 -142.060 137.255 -141.420 ;
        RECT 142.095 -142.060 142.415 -141.420 ;
        RECT 147.255 -142.060 147.575 -141.420 ;
        RECT 134.355 -143.815 134.675 -143.175 ;
        RECT 126.765 -145.525 127.085 -144.885 ;
        RECT 133.555 -144.890 133.875 -144.885 ;
        RECT 133.555 -145.525 134.195 -144.890 ;
        RECT 122.940 -146.815 124.645 -146.810 ;
        RECT 122.940 -147.135 125.370 -146.815 ;
        RECT 125.910 -146.910 126.660 -146.815 ;
        RECT 125.905 -147.135 126.660 -146.910 ;
        RECT 122.940 -152.545 123.170 -147.135 ;
        RECT 123.325 -147.140 124.075 -147.135 ;
        RECT 124.615 -147.140 125.365 -147.135 ;
        RECT 125.905 -147.140 126.655 -147.135 ;
        RECT 124.230 -151.655 124.460 -147.345 ;
        RECT 124.230 -152.345 124.465 -151.655 ;
        RECT 124.235 -152.545 124.465 -152.345 ;
        RECT 122.940 -152.865 125.370 -152.545 ;
        RECT 125.910 -152.550 126.660 -152.545 ;
        RECT 125.905 -152.780 126.660 -152.550 ;
        RECT 125.910 -152.865 126.660 -152.780 ;
        RECT 122.940 -152.870 124.465 -152.865 ;
        RECT 125.960 -152.870 126.600 -152.865 ;
        RECT 124.235 -161.820 124.465 -152.870 ;
        RECT 126.810 -154.150 127.040 -145.525 ;
        RECT 133.875 -145.530 134.195 -145.525 ;
        RECT 129.215 -146.815 130.910 -146.810 ;
        RECT 127.200 -146.910 127.950 -146.815 ;
        RECT 128.490 -146.910 130.910 -146.815 ;
        RECT 127.195 -147.135 127.950 -146.910 ;
        RECT 128.485 -147.135 130.910 -146.910 ;
        RECT 127.195 -147.140 127.945 -147.135 ;
        RECT 128.485 -147.140 129.235 -147.135 ;
        RECT 129.775 -147.140 130.525 -147.135 ;
        RECT 129.390 -151.665 129.620 -147.345 ;
        RECT 129.390 -152.345 129.625 -151.665 ;
        RECT 129.395 -152.540 129.625 -152.345 ;
        RECT 130.680 -152.540 130.910 -147.135 ;
        RECT 133.495 -147.140 134.245 -146.820 ;
        RECT 129.215 -152.545 130.910 -152.540 ;
        RECT 127.200 -152.550 127.950 -152.545 ;
        RECT 128.490 -152.550 130.910 -152.545 ;
        RECT 127.195 -152.780 127.950 -152.550 ;
        RECT 128.485 -152.780 130.910 -152.550 ;
        RECT 127.200 -152.865 127.950 -152.780 ;
        RECT 128.490 -152.865 130.910 -152.780 ;
        RECT 127.250 -152.870 127.890 -152.865 ;
        RECT 128.540 -152.870 129.180 -152.865 ;
        RECT 126.765 -154.790 127.085 -154.150 ;
        RECT 124.670 -161.820 125.310 -161.730 ;
        RECT 122.940 -162.050 124.465 -161.820 ;
        RECT 124.615 -162.050 125.365 -161.820 ;
        RECT 122.940 -162.870 123.170 -162.050 ;
        RECT 124.230 -162.870 124.465 -162.050 ;
        RECT 122.940 -163.100 124.465 -162.870 ;
        RECT 124.615 -163.100 125.365 -162.870 ;
        RECT 124.670 -163.190 125.310 -163.100 ;
        RECT 125.520 -163.745 125.750 -162.210 ;
        RECT 126.810 -162.710 127.040 -154.790 ;
        RECT 128.540 -161.820 129.180 -161.730 ;
        RECT 129.395 -161.820 129.625 -152.865 ;
        RECT 133.495 -152.870 134.245 -152.550 ;
        RECT 134.400 -156.020 134.630 -143.815 ;
        RECT 134.785 -147.140 135.535 -146.820 ;
        RECT 136.075 -147.140 136.825 -146.820 ;
        RECT 134.785 -152.870 135.535 -152.550 ;
        RECT 136.075 -152.870 136.825 -152.550 ;
        RECT 134.355 -156.660 134.675 -156.020 ;
        RECT 136.980 -157.620 137.210 -142.060 ;
        RECT 139.515 -143.815 139.835 -143.175 ;
        RECT 137.365 -147.140 138.115 -146.820 ;
        RECT 138.655 -147.140 139.405 -146.820 ;
        RECT 139.565 -147.345 139.795 -143.815 ;
        RECT 139.945 -147.140 140.695 -146.820 ;
        RECT 141.235 -147.140 141.985 -146.820 ;
        RECT 139.560 -152.345 139.795 -147.345 ;
        RECT 137.365 -152.870 138.115 -152.550 ;
        RECT 138.655 -152.870 139.405 -152.550 ;
        RECT 139.565 -156.020 139.795 -152.345 ;
        RECT 139.945 -152.870 140.695 -152.550 ;
        RECT 141.235 -152.870 141.985 -152.550 ;
        RECT 139.515 -156.660 139.835 -156.020 ;
        RECT 136.935 -158.260 137.255 -157.620 ;
        RECT 128.485 -162.050 129.235 -161.820 ;
        RECT 129.395 -162.050 130.910 -161.820 ;
        RECT 133.485 -162.050 134.235 -161.730 ;
        RECT 134.775 -162.050 135.525 -161.730 ;
        RECT 136.065 -162.050 136.815 -161.730 ;
        RECT 137.355 -162.050 138.105 -161.730 ;
        RECT 138.645 -162.050 139.395 -161.730 ;
        RECT 129.395 -162.210 129.625 -162.050 ;
        RECT 128.100 -163.735 128.330 -162.210 ;
        RECT 129.390 -162.225 129.625 -162.210 ;
        RECT 129.390 -162.870 129.620 -162.225 ;
        RECT 130.680 -162.870 130.910 -162.050 ;
        RECT 139.565 -162.210 139.795 -156.660 ;
        RECT 142.140 -157.620 142.370 -142.060 ;
        RECT 144.675 -143.815 144.995 -143.175 ;
        RECT 142.525 -147.140 143.275 -146.820 ;
        RECT 143.815 -147.140 144.565 -146.820 ;
        RECT 142.525 -152.870 143.275 -152.550 ;
        RECT 143.815 -152.870 144.565 -152.550 ;
        RECT 144.720 -156.020 144.950 -143.815 ;
        RECT 145.105 -147.140 145.855 -146.820 ;
        RECT 146.395 -147.140 147.145 -146.820 ;
        RECT 145.105 -152.870 145.855 -152.550 ;
        RECT 146.395 -152.870 147.145 -152.550 ;
        RECT 144.675 -156.660 144.995 -156.020 ;
        RECT 147.300 -157.620 147.530 -142.060 ;
        RECT 153.535 -146.135 153.855 -144.800 ;
        RECT 147.685 -147.140 148.435 -146.820 ;
        RECT 152.730 -146.910 153.370 -146.820 ;
        RECT 152.675 -147.140 153.425 -146.910 ;
        RECT 147.685 -152.870 148.435 -152.550 ;
        RECT 152.675 -152.780 153.425 -152.550 ;
        RECT 152.730 -152.870 153.370 -152.780 ;
        RECT 153.580 -153.760 153.810 -146.135 ;
        RECT 154.020 -146.910 154.660 -146.820 ;
        RECT 155.310 -146.910 155.950 -143.175 ;
        RECT 156.160 -144.855 156.390 -144.575 ;
        RECT 156.115 -146.135 156.435 -144.855 ;
        RECT 153.965 -147.140 154.715 -146.910 ;
        RECT 155.255 -147.140 156.005 -146.910 ;
        RECT 153.965 -152.780 154.715 -152.550 ;
        RECT 155.255 -152.780 156.005 -152.550 ;
        RECT 154.020 -152.870 154.660 -152.780 ;
        RECT 150.955 -155.040 151.275 -153.760 ;
        RECT 153.535 -155.040 153.855 -153.760 ;
        RECT 142.095 -158.260 142.415 -157.620 ;
        RECT 147.260 -158.260 147.580 -157.620 ;
        RECT 139.935 -162.050 140.685 -161.730 ;
        RECT 141.225 -162.050 141.975 -161.730 ;
        RECT 142.515 -162.050 143.265 -161.730 ;
        RECT 143.805 -162.050 144.555 -161.730 ;
        RECT 145.095 -162.050 145.845 -161.730 ;
        RECT 150.140 -161.820 150.780 -161.730 ;
        RECT 150.085 -162.050 150.835 -161.820 ;
        RECT 128.485 -163.100 129.235 -162.870 ;
        RECT 129.390 -163.100 130.910 -162.870 ;
        RECT 128.540 -163.190 129.180 -163.100 ;
        RECT 133.485 -163.190 134.235 -162.870 ;
        RECT 134.390 -163.735 134.620 -162.210 ;
        RECT 134.775 -163.190 135.525 -162.870 ;
        RECT 136.065 -163.190 136.815 -162.870 ;
        RECT 136.970 -163.735 137.200 -162.210 ;
        RECT 139.550 -162.710 139.795 -162.210 ;
        RECT 137.355 -163.190 138.105 -162.870 ;
        RECT 138.645 -163.190 139.395 -162.870 ;
        RECT 125.475 -164.385 125.795 -163.745 ;
        RECT 128.055 -164.375 128.375 -163.735 ;
        RECT 134.345 -164.375 134.665 -163.735 ;
        RECT 136.925 -164.375 137.245 -163.735 ;
        RECT 134.390 -164.385 134.620 -164.375 ;
        RECT 136.970 -164.385 137.200 -164.375 ;
        RECT 123.675 -166.710 125.195 -166.480 ;
        RECT 123.675 -167.620 123.905 -166.710 ;
        RECT 124.965 -167.620 125.195 -166.710 ;
        RECT 129.340 -167.035 129.660 -166.395 ;
        RECT 123.675 -167.850 125.195 -167.620 ;
        RECT 123.675 -168.160 123.905 -167.850 ;
        RECT 124.965 -168.160 125.195 -167.850 ;
        RECT 123.675 -168.390 125.195 -168.160 ;
        RECT 125.350 -168.390 126.100 -167.925 ;
        RECT 126.640 -168.390 127.785 -167.925 ;
        RECT 123.675 -169.300 123.905 -168.390 ;
        RECT 124.965 -169.300 125.195 -168.390 ;
        RECT 127.545 -169.300 127.785 -168.390 ;
        RECT 123.675 -169.530 125.195 -169.300 ;
        RECT 123.675 -169.840 123.905 -169.530 ;
        RECT 124.965 -169.840 125.195 -169.530 ;
        RECT 125.350 -169.665 126.100 -169.300 ;
        RECT 126.640 -169.665 127.785 -169.300 ;
        RECT 123.675 -170.070 125.195 -169.840 ;
        RECT 123.675 -170.980 123.905 -170.070 ;
        RECT 124.965 -170.980 125.195 -170.070 ;
        RECT 123.675 -171.210 125.195 -170.980 ;
        RECT 124.965 -173.620 125.195 -171.210 ;
        RECT 124.800 -174.400 125.555 -173.620 ;
        RECT 124.800 -174.860 125.550 -174.540 ;
        RECT 124.800 -175.850 125.045 -174.860 ;
        RECT 125.295 -175.850 125.550 -174.860 ;
        RECT 124.800 -176.170 125.550 -175.850 ;
        RECT 125.700 -174.570 126.020 -172.600 ;
        RECT 126.995 -174.570 127.225 -172.650 ;
        RECT 125.700 -174.890 127.225 -174.570 ;
        RECT 125.700 -175.820 126.020 -174.890 ;
        RECT 126.995 -175.820 127.225 -174.890 ;
        RECT 125.700 -176.140 127.225 -175.820 ;
        RECT 124.800 -177.090 125.550 -176.310 ;
        RECT 125.040 -179.320 125.360 -177.090 ;
        RECT 125.700 -178.160 126.020 -176.140 ;
        RECT 125.700 -178.330 125.950 -178.160 ;
        RECT 126.995 -178.330 127.225 -176.140 ;
        RECT 127.545 -178.155 127.785 -169.665 ;
        RECT 129.395 -171.930 129.625 -167.035 ;
        RECT 129.845 -167.945 130.485 -167.925 ;
        RECT 129.780 -168.175 130.530 -167.945 ;
        RECT 129.845 -168.245 130.485 -168.175 ;
        RECT 134.775 -168.260 135.515 -168.030 ;
        RECT 139.555 -168.245 139.795 -162.710 ;
        RECT 139.935 -163.190 140.685 -162.870 ;
        RECT 141.225 -163.190 141.975 -162.870 ;
        RECT 142.130 -163.735 142.360 -162.210 ;
        RECT 142.515 -163.190 143.265 -162.870 ;
        RECT 143.805 -163.190 144.555 -162.870 ;
        RECT 144.710 -163.735 144.940 -162.210 ;
        RECT 150.990 -162.255 151.230 -155.040 ;
        RECT 155.310 -156.660 155.950 -152.780 ;
        RECT 156.160 -153.755 156.390 -146.135 ;
        RECT 156.600 -146.910 157.240 -143.175 ;
        RECT 158.740 -144.855 158.970 -144.550 ;
        RECT 158.695 -146.135 159.015 -144.855 ;
        RECT 157.890 -146.910 158.530 -146.820 ;
        RECT 156.545 -147.140 157.295 -146.910 ;
        RECT 157.835 -147.140 158.585 -146.910 ;
        RECT 156.545 -152.780 157.295 -152.550 ;
        RECT 157.835 -152.780 158.585 -152.550 ;
        RECT 156.600 -152.880 157.240 -152.780 ;
        RECT 157.890 -152.870 158.530 -152.780 ;
        RECT 156.115 -155.040 156.435 -153.755 ;
        RECT 153.570 -157.620 153.800 -157.570 ;
        RECT 153.535 -158.260 153.855 -157.620 ;
        RECT 151.430 -161.820 152.070 -161.730 ;
        RECT 152.720 -161.820 153.360 -161.730 ;
        RECT 153.570 -161.820 153.800 -158.260 ;
        RECT 154.010 -161.820 154.650 -161.730 ;
        RECT 155.300 -161.820 155.940 -161.730 ;
        RECT 151.375 -162.050 152.125 -161.820 ;
        RECT 152.665 -162.050 154.705 -161.820 ;
        RECT 155.245 -162.050 155.995 -161.820 ;
        RECT 150.990 -162.710 151.220 -162.255 ;
        RECT 153.570 -162.870 153.800 -162.050 ;
        RECT 156.150 -162.240 156.390 -155.040 ;
        RECT 156.600 -156.020 157.235 -152.880 ;
        RECT 158.740 -153.760 158.970 -146.135 ;
        RECT 159.180 -146.910 159.820 -146.820 ;
        RECT 159.125 -147.140 159.875 -146.910 ;
        RECT 159.125 -152.780 159.875 -152.550 ;
        RECT 159.180 -152.870 159.820 -152.780 ;
        RECT 158.695 -155.040 159.015 -153.760 ;
        RECT 156.595 -156.660 157.235 -156.020 ;
        RECT 156.590 -161.820 157.230 -161.730 ;
        RECT 156.535 -162.050 157.285 -161.820 ;
        RECT 156.150 -162.710 156.380 -162.240 ;
        RECT 145.095 -163.190 145.845 -162.870 ;
        RECT 150.085 -163.100 150.835 -162.870 ;
        RECT 151.375 -163.100 152.125 -162.870 ;
        RECT 152.665 -163.100 154.705 -162.870 ;
        RECT 155.245 -163.100 155.995 -162.870 ;
        RECT 156.535 -163.100 157.285 -162.870 ;
        RECT 150.140 -163.190 150.780 -163.100 ;
        RECT 151.430 -163.190 152.070 -163.100 ;
        RECT 152.720 -163.190 153.360 -163.100 ;
        RECT 154.010 -163.190 154.650 -163.100 ;
        RECT 155.300 -163.190 155.940 -163.100 ;
        RECT 156.590 -163.190 157.230 -163.100 ;
        RECT 142.085 -164.375 142.405 -163.735 ;
        RECT 144.665 -164.375 144.985 -163.735 ;
        RECT 142.130 -164.385 142.360 -164.375 ;
        RECT 144.710 -164.385 144.940 -164.375 ;
        RECT 151.070 -167.910 153.175 -167.660 ;
        RECT 157.445 -167.910 159.550 -167.660 ;
        RECT 160.435 -168.075 161.495 -153.755 ;
        RECT 132.535 -169.000 132.945 -168.500 ;
        RECT 133.680 -168.630 134.615 -168.465 ;
        RECT 129.780 -169.665 130.530 -169.345 ;
        RECT 129.340 -172.570 129.660 -171.930 ;
        RECT 130.100 -172.570 130.420 -171.930 ;
        RECT 127.990 -174.710 128.630 -174.590 ;
        RECT 127.940 -174.940 128.690 -174.710 ;
        RECT 127.940 -175.990 128.690 -175.760 ;
        RECT 128.005 -176.110 128.645 -175.990 ;
        RECT 130.135 -178.155 130.365 -172.570 ;
        RECT 132.715 -174.640 132.945 -169.000 ;
        RECT 130.575 -174.710 131.215 -174.640 ;
        RECT 131.860 -174.710 132.945 -174.640 ;
        RECT 130.520 -174.940 131.270 -174.710 ;
        RECT 131.810 -174.940 132.945 -174.710 ;
        RECT 130.575 -174.960 131.215 -174.940 ;
        RECT 131.860 -174.960 132.945 -174.940 ;
        RECT 132.715 -175.720 132.945 -174.960 ;
        RECT 130.570 -175.760 131.210 -175.720 ;
        RECT 131.865 -175.760 132.945 -175.720 ;
        RECT 130.520 -175.990 131.270 -175.760 ;
        RECT 131.810 -175.990 132.945 -175.760 ;
        RECT 130.570 -176.040 131.210 -175.990 ;
        RECT 131.865 -176.040 132.945 -175.990 ;
        RECT 132.715 -178.155 132.945 -176.040 ;
        RECT 133.675 -169.055 134.615 -168.630 ;
        RECT 133.675 -170.825 134.315 -169.055 ;
        RECT 135.025 -169.260 135.255 -168.260 ;
        RECT 139.510 -168.885 139.830 -168.245 ;
        RECT 149.245 -168.490 151.585 -168.245 ;
        RECT 160.365 -168.485 161.495 -168.075 ;
        RECT 158.490 -168.490 161.495 -168.485 ;
        RECT 149.245 -168.740 153.175 -168.490 ;
        RECT 157.445 -168.740 161.495 -168.490 ;
        RECT 149.245 -168.885 151.585 -168.740 ;
        RECT 160.365 -168.745 161.495 -168.740 ;
        RECT 134.775 -170.040 135.515 -169.260 ;
        RECT 151.070 -169.570 153.175 -169.320 ;
        RECT 157.445 -169.570 159.550 -169.320 ;
        RECT 133.675 -178.325 133.890 -170.825 ;
        RECT 134.080 -178.325 134.315 -170.825 ;
        RECT 134.775 -170.960 135.515 -170.180 ;
        RECT 135.025 -171.890 135.255 -170.960 ;
        RECT 150.200 -171.580 152.305 -171.330 ;
        RECT 158.325 -171.580 160.430 -171.330 ;
        RECT 134.510 -172.530 134.830 -171.890 ;
        RECT 134.975 -172.530 135.295 -171.890 ;
        RECT 148.725 -172.410 152.305 -172.160 ;
        RECT 134.565 -175.600 134.795 -172.530 ;
        RECT 135.010 -174.960 135.650 -174.640 ;
        RECT 125.700 -178.650 126.020 -178.330 ;
        RECT 126.950 -178.650 127.270 -178.330 ;
        RECT 133.675 -178.645 134.315 -178.325 ;
        RECT 134.535 -178.325 134.795 -175.600 ;
        RECT 135.005 -176.040 135.645 -175.720 ;
        RECT 148.725 -175.830 149.045 -172.410 ;
        RECT 150.200 -173.240 152.305 -172.990 ;
        RECT 158.325 -173.240 160.430 -172.990 ;
        RECT 150.660 -175.250 152.765 -175.000 ;
        RECT 157.905 -175.250 160.010 -175.000 ;
        RECT 148.725 -176.080 152.765 -175.830 ;
        RECT 157.905 -176.080 160.010 -175.830 ;
        RECT 150.660 -176.910 152.765 -176.660 ;
        RECT 157.905 -176.910 160.010 -176.660 ;
        RECT 134.535 -178.645 134.855 -178.325 ;
        RECT 127.005 -179.320 127.325 -179.260 ;
        RECT 133.170 -179.320 133.490 -179.140 ;
        RECT 123.260 -179.570 125.365 -179.320 ;
        RECT 127.005 -179.570 129.110 -179.320 ;
        RECT 131.385 -179.570 133.490 -179.320 ;
        RECT 135.130 -179.320 135.450 -179.140 ;
        RECT 135.130 -179.570 137.235 -179.320 ;
        RECT 127.005 -179.580 127.325 -179.570 ;
        RECT 164.630 -187.370 165.270 -187.280 ;
        RECT 165.920 -187.370 166.560 -187.280 ;
        RECT 167.210 -187.370 167.850 -187.280 ;
        RECT 168.500 -187.370 169.140 -187.280 ;
        RECT 169.790 -187.370 170.430 -187.280 ;
        RECT 171.075 -187.370 171.715 -187.280 ;
        RECT 172.365 -187.370 173.005 -187.280 ;
        RECT 173.655 -187.370 174.295 -187.280 ;
        RECT 174.950 -187.370 175.590 -187.280 ;
        RECT 176.240 -187.370 176.880 -187.280 ;
        RECT 177.525 -187.370 178.165 -187.280 ;
        RECT 178.820 -187.370 179.460 -187.280 ;
        RECT 180.115 -187.370 180.755 -187.280 ;
        RECT 181.395 -187.370 182.035 -187.280 ;
        RECT 182.690 -187.370 183.330 -187.280 ;
        RECT 183.980 -187.370 184.620 -187.280 ;
        RECT 185.265 -187.370 185.905 -187.280 ;
        RECT 186.555 -187.370 187.195 -187.280 ;
        RECT 187.850 -187.370 188.490 -187.280 ;
        RECT 189.135 -187.370 189.775 -187.280 ;
        RECT 190.430 -187.370 191.070 -187.280 ;
        RECT 191.715 -187.370 192.355 -187.280 ;
        RECT 193.010 -187.370 193.650 -187.280 ;
        RECT 194.295 -187.370 194.935 -187.280 ;
        RECT 195.590 -187.370 196.230 -187.280 ;
        RECT 164.575 -187.600 165.325 -187.370 ;
        RECT 165.865 -187.600 166.615 -187.370 ;
        RECT 167.155 -187.600 167.905 -187.370 ;
        RECT 168.445 -187.600 169.195 -187.370 ;
        RECT 169.735 -187.600 170.485 -187.370 ;
        RECT 171.025 -187.600 171.775 -187.370 ;
        RECT 172.315 -187.600 173.065 -187.370 ;
        RECT 173.605 -187.600 174.355 -187.370 ;
        RECT 174.895 -187.600 175.645 -187.370 ;
        RECT 176.185 -187.600 176.935 -187.370 ;
        RECT 177.475 -187.600 178.225 -187.370 ;
        RECT 178.765 -187.600 179.515 -187.370 ;
        RECT 180.055 -187.600 180.805 -187.370 ;
        RECT 181.345 -187.600 182.095 -187.370 ;
        RECT 182.635 -187.600 183.385 -187.370 ;
        RECT 183.925 -187.600 184.675 -187.370 ;
        RECT 185.215 -187.600 185.965 -187.370 ;
        RECT 186.505 -187.600 187.255 -187.370 ;
        RECT 187.795 -187.600 188.545 -187.370 ;
        RECT 189.085 -187.600 189.835 -187.370 ;
        RECT 190.375 -187.600 191.125 -187.370 ;
        RECT 191.665 -187.600 192.415 -187.370 ;
        RECT 192.955 -187.600 193.705 -187.370 ;
        RECT 194.245 -187.600 194.995 -187.370 ;
        RECT 195.535 -187.600 196.285 -187.370 ;
      LAYER met2 ;
        RECT 136.935 -142.060 147.575 -141.420 ;
        RECT 164.355 -141.935 196.505 -140.650 ;
        RECT 134.355 -143.815 157.240 -143.175 ;
        RECT 126.765 -145.525 148.375 -144.885 ;
        RECT 126.810 -145.530 148.375 -145.525 ;
        RECT 124.620 -147.135 129.180 -146.815 ;
        RECT 133.550 -146.820 134.240 -145.530 ;
        RECT 140.625 -146.820 141.315 -145.530 ;
        RECT 147.685 -146.820 148.375 -145.530 ;
        RECT 153.535 -146.135 196.500 -144.800 ;
        RECT 152.730 -146.820 159.810 -146.810 ;
        RECT 124.670 -147.140 125.310 -147.135 ;
        RECT 125.960 -147.140 126.600 -147.135 ;
        RECT 127.250 -147.140 127.890 -147.135 ;
        RECT 128.535 -147.140 129.175 -147.135 ;
        RECT 133.550 -147.140 148.380 -146.820 ;
        RECT 152.730 -147.140 159.820 -146.820 ;
        RECT 124.670 -152.865 129.180 -152.545 ;
        RECT 125.960 -152.870 126.600 -152.865 ;
        RECT 127.250 -152.870 127.890 -152.865 ;
        RECT 128.540 -152.870 129.180 -152.865 ;
        RECT 133.550 -152.870 148.380 -152.550 ;
        RECT 133.550 -154.150 134.240 -152.870 ;
        RECT 140.655 -154.150 141.345 -152.870 ;
        RECT 147.690 -154.150 148.380 -152.870 ;
        RECT 152.715 -152.880 159.820 -152.550 ;
        RECT 150.960 -153.760 196.500 -153.755 ;
        RECT 126.765 -154.790 148.380 -154.150 ;
        RECT 126.810 -154.795 148.380 -154.790 ;
        RECT 150.955 -155.040 196.500 -153.760 ;
        RECT 134.355 -156.660 157.235 -156.020 ;
        RECT 136.935 -158.260 153.855 -157.620 ;
        RECT 124.670 -162.050 125.310 -161.730 ;
        RECT 128.540 -162.050 129.180 -161.730 ;
        RECT 133.540 -162.080 145.790 -161.710 ;
        RECT 150.140 -162.050 157.230 -161.730 ;
        RECT 124.670 -163.190 125.310 -162.870 ;
        RECT 128.540 -163.190 129.180 -162.870 ;
        RECT 133.540 -163.215 145.790 -162.845 ;
        RECT 150.140 -163.190 157.230 -162.870 ;
        RECT 125.475 -164.385 144.985 -163.735 ;
        RECT 129.340 -167.035 145.650 -166.395 ;
        RECT 125.390 -168.245 130.485 -167.925 ;
        RECT 139.510 -168.885 150.005 -168.245 ;
        RECT 125.350 -169.665 130.485 -169.345 ;
        RECT 134.775 -170.960 135.515 -169.260 ;
        RECT 129.340 -172.570 130.420 -171.930 ;
        RECT 134.510 -172.530 135.295 -171.890 ;
        RECT 124.785 -173.395 149.225 -172.755 ;
        RECT 124.800 -174.400 125.555 -173.620 ;
        RECT 124.800 -174.860 125.550 -174.400 ;
        RECT 126.145 -174.590 128.615 -174.570 ;
        RECT 126.145 -174.890 128.630 -174.590 ;
        RECT 127.990 -174.910 128.630 -174.890 ;
        RECT 130.575 -174.960 135.650 -174.640 ;
        RECT 128.005 -175.820 128.645 -175.790 ;
        RECT 124.800 -177.090 125.550 -175.850 ;
        RECT 126.145 -176.140 128.645 -175.820 ;
        RECT 130.570 -176.040 135.645 -175.720 ;
        RECT 125.700 -178.650 127.325 -178.330 ;
        RECT 127.005 -179.580 127.325 -178.650 ;
        RECT 133.170 -178.645 134.315 -178.325 ;
        RECT 134.535 -178.645 135.450 -178.325 ;
        RECT 133.170 -179.460 133.490 -178.645 ;
        RECT 135.130 -179.460 135.450 -178.645 ;
        RECT 164.360 -187.600 196.505 -186.315 ;
      LAYER met3 ;
        RECT 140.125 -159.440 141.810 -144.885 ;
        RECT 124.785 -173.395 125.190 -161.705 ;
        RECT 128.655 -173.395 129.060 -161.705 ;
        RECT 133.675 -167.035 134.045 -161.710 ;
        RECT 140.125 -190.355 141.805 -159.440 ;
        RECT 145.280 -162.845 145.650 -161.710 ;
        RECT 145.275 -163.215 145.650 -162.845 ;
        RECT 145.280 -167.035 145.650 -163.215 ;
        RECT 164.370 -187.600 165.530 -140.650 ;
        RECT 166.950 -187.600 168.180 -140.650 ;
        RECT 192.750 -187.600 193.910 -140.650 ;
        RECT 195.330 -187.600 196.490 -140.650 ;
        RECT 121.455 -204.080 137.315 -191.680 ;
        RECT 138.515 -204.080 154.375 -191.680 ;
        RECT 155.575 -204.080 171.435 -191.680 ;
        RECT 121.455 -217.680 137.315 -205.280 ;
        RECT 138.515 -217.680 154.375 -205.280 ;
        RECT 155.575 -217.680 171.435 -205.280 ;
        RECT 121.455 -231.280 137.315 -218.880 ;
        RECT 138.515 -231.280 154.375 -218.880 ;
        RECT 155.575 -231.280 171.435 -218.880 ;
      LAYER met4 ;
        RECT 170.915 -188.565 171.860 -188.560 ;
        RECT 136.795 -190.355 171.860 -188.565 ;
        RECT 136.795 -231.880 137.740 -190.355 ;
        RECT 153.855 -231.880 154.800 -190.355 ;
        RECT 170.915 -231.880 171.860 -190.355 ;
  END
END LDO_V22
END LIBRARY

